VERSION 5.8 ;
BUSBITCHARS "[]" ;
DIVIDERCHAR "/" ;
UNITS
    DATABASE MICRONS 1000 ;
END UNITS

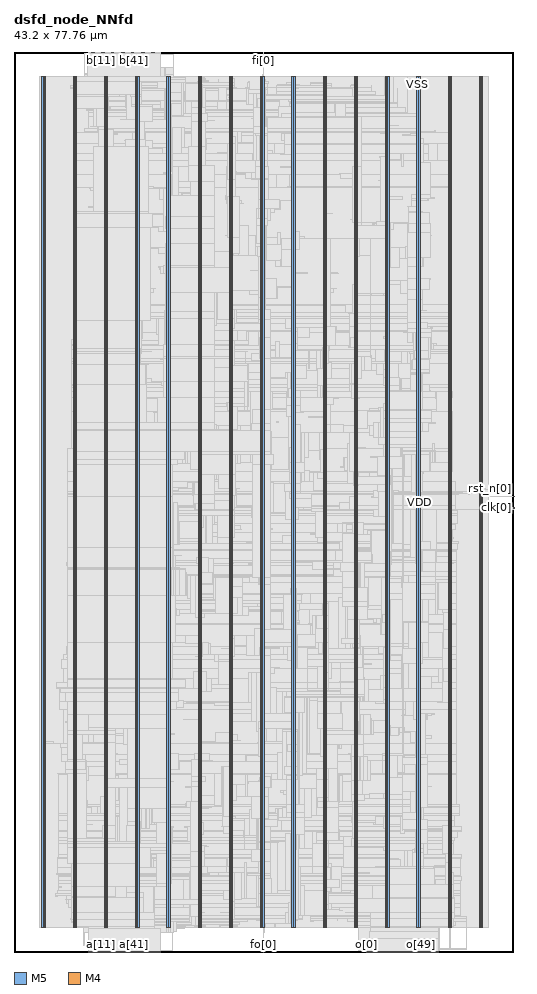
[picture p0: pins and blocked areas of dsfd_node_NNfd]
MACRO dsfd_node_NNfd
  FOREIGN dsfd_node_NNfd 0 0 ;
  CLASS BLOCK ;
  SIZE 43.2 BY 77.76 ;
  PIN a[0]
    DIRECTION INPUT ;
    USE SIGNAL ;
    PORT
      LAYER M5 ;
        RECT  6.432 0 6.456 0.084 ;
    END
  END a[0]
  PIN a[10]
    DIRECTION INPUT ;
    USE SIGNAL ;
    PORT
      LAYER M5 ;
        RECT  7.392 0 7.416 0.084 ;
    END
  END a[10]
  PIN a[11]
    DIRECTION INPUT ;
    USE SIGNAL ;
    PORT
      LAYER M5 ;
        RECT  7.488 0 7.512 0.084 ;
    END
  END a[11]
  PIN a[12]
    DIRECTION INPUT ;
    USE SIGNAL ;
    PORT
      LAYER M5 ;
        RECT  7.584 0 7.608 0.084 ;
    END
  END a[12]
  PIN a[13]
    DIRECTION INPUT ;
    USE SIGNAL ;
    PORT
      LAYER M5 ;
        RECT  7.68 0 7.704 0.084 ;
    END
  END a[13]
  PIN a[14]
    DIRECTION INPUT ;
    USE SIGNAL ;
    PORT
      LAYER M5 ;
        RECT  7.776 0 7.8 0.084 ;
    END
  END a[14]
  PIN a[15]
    DIRECTION INPUT ;
    USE SIGNAL ;
    PORT
      LAYER M5 ;
        RECT  7.872 0 7.896 0.084 ;
    END
  END a[15]
  PIN a[16]
    DIRECTION INPUT ;
    USE SIGNAL ;
    PORT
      LAYER M5 ;
        RECT  7.968 0 7.992 0.084 ;
    END
  END a[16]
  PIN a[17]
    DIRECTION INPUT ;
    USE SIGNAL ;
    PORT
      LAYER M5 ;
        RECT  8.064 0 8.088 0.084 ;
    END
  END a[17]
  PIN a[18]
    DIRECTION INPUT ;
    USE SIGNAL ;
    PORT
      LAYER M5 ;
        RECT  8.16 0 8.184 0.084 ;
    END
  END a[18]
  PIN a[19]
    DIRECTION INPUT ;
    USE SIGNAL ;
    PORT
      LAYER M5 ;
        RECT  8.256 0 8.28 0.084 ;
    END
  END a[19]
  PIN a[1]
    DIRECTION INPUT ;
    USE SIGNAL ;
    PORT
      LAYER M5 ;
        RECT  6.528 0 6.552 0.084 ;
    END
  END a[1]
  PIN a[20]
    DIRECTION INPUT ;
    USE SIGNAL ;
    PORT
      LAYER M5 ;
        RECT  8.352 0 8.376 0.084 ;
    END
  END a[20]
  PIN a[21]
    DIRECTION INPUT ;
    USE SIGNAL ;
    PORT
      LAYER M5 ;
        RECT  8.448 0 8.472 0.084 ;
    END
  END a[21]
  PIN a[22]
    DIRECTION INPUT ;
    USE SIGNAL ;
    PORT
      LAYER M5 ;
        RECT  8.544 0 8.568 0.084 ;
    END
  END a[22]
  PIN a[23]
    DIRECTION INPUT ;
    USE SIGNAL ;
    PORT
      LAYER M5 ;
        RECT  8.64 0 8.664 0.084 ;
    END
  END a[23]
  PIN a[24]
    DIRECTION INPUT ;
    USE SIGNAL ;
    PORT
      LAYER M5 ;
        RECT  8.736 0 8.76 0.084 ;
    END
  END a[24]
  PIN a[25]
    DIRECTION INPUT ;
    USE SIGNAL ;
    PORT
      LAYER M5 ;
        RECT  8.832 0 8.856 0.084 ;
    END
  END a[25]
  PIN a[26]
    DIRECTION INPUT ;
    USE SIGNAL ;
    PORT
      LAYER M5 ;
        RECT  8.928 0 8.952 0.084 ;
    END
  END a[26]
  PIN a[27]
    DIRECTION INPUT ;
    USE SIGNAL ;
    PORT
      LAYER M5 ;
        RECT  9.024 0 9.048 0.084 ;
    END
  END a[27]
  PIN a[28]
    DIRECTION INPUT ;
    USE SIGNAL ;
    PORT
      LAYER M5 ;
        RECT  9.12 0 9.144 0.084 ;
    END
  END a[28]
  PIN a[29]
    DIRECTION INPUT ;
    USE SIGNAL ;
    PORT
      LAYER M5 ;
        RECT  9.216 0 9.24 0.084 ;
    END
  END a[29]
  PIN a[2]
    DIRECTION INPUT ;
    USE SIGNAL ;
    PORT
      LAYER M5 ;
        RECT  6.624 0 6.648 0.084 ;
    END
  END a[2]
  PIN a[30]
    DIRECTION INPUT ;
    USE SIGNAL ;
    PORT
      LAYER M5 ;
        RECT  9.312 0 9.336 0.084 ;
    END
  END a[30]
  PIN a[31]
    DIRECTION INPUT ;
    USE SIGNAL ;
    PORT
      LAYER M5 ;
        RECT  9.408 0 9.432 0.084 ;
    END
  END a[31]
  PIN a[32]
    DIRECTION INPUT ;
    USE SIGNAL ;
    PORT
      LAYER M5 ;
        RECT  9.504 0 9.528 0.084 ;
    END
  END a[32]
  PIN a[33]
    DIRECTION INPUT ;
    USE SIGNAL ;
    PORT
      LAYER M5 ;
        RECT  9.6 0 9.624 0.084 ;
    END
  END a[33]
  PIN a[34]
    DIRECTION INPUT ;
    USE SIGNAL ;
    PORT
      LAYER M5 ;
        RECT  9.696 0 9.72 0.084 ;
    END
  END a[34]
  PIN a[35]
    DIRECTION INPUT ;
    USE SIGNAL ;
    PORT
      LAYER M5 ;
        RECT  9.792 0 9.816 0.084 ;
    END
  END a[35]
  PIN a[36]
    DIRECTION INPUT ;
    USE SIGNAL ;
    PORT
      LAYER M5 ;
        RECT  9.888 0 9.912 0.084 ;
    END
  END a[36]
  PIN a[37]
    DIRECTION INPUT ;
    USE SIGNAL ;
    PORT
      LAYER M5 ;
        RECT  9.984 0 10.008 0.084 ;
    END
  END a[37]
  PIN a[38]
    DIRECTION INPUT ;
    USE SIGNAL ;
    PORT
      LAYER M5 ;
        RECT  10.08 0 10.104 0.084 ;
    END
  END a[38]
  PIN a[39]
    DIRECTION INPUT ;
    USE SIGNAL ;
    PORT
      LAYER M5 ;
        RECT  10.176 0 10.2 0.084 ;
    END
  END a[39]
  PIN a[3]
    DIRECTION INPUT ;
    USE SIGNAL ;
    PORT
      LAYER M5 ;
        RECT  6.72 0 6.744 0.084 ;
    END
  END a[3]
  PIN a[40]
    DIRECTION INPUT ;
    USE SIGNAL ;
    PORT
      LAYER M5 ;
        RECT  10.272 0 10.296 0.084 ;
    END
  END a[40]
  PIN a[41]
    DIRECTION INPUT ;
    USE SIGNAL ;
    PORT
      LAYER M5 ;
        RECT  10.368 0 10.392 0.084 ;
    END
  END a[41]
  PIN a[42]
    DIRECTION INPUT ;
    USE SIGNAL ;
    PORT
      LAYER M5 ;
        RECT  10.464 0 10.488 0.084 ;
    END
  END a[42]
  PIN a[43]
    DIRECTION INPUT ;
    USE SIGNAL ;
    PORT
      LAYER M5 ;
        RECT  10.56 0 10.584 0.084 ;
    END
  END a[43]
  PIN a[44]
    DIRECTION INPUT ;
    USE SIGNAL ;
    PORT
      LAYER M5 ;
        RECT  10.656 0 10.68 0.084 ;
    END
  END a[44]
  PIN a[45]
    DIRECTION INPUT ;
    USE SIGNAL ;
    PORT
      LAYER M5 ;
        RECT  10.752 0 10.776 0.084 ;
    END
  END a[45]
  PIN a[46]
    DIRECTION INPUT ;
    USE SIGNAL ;
    PORT
      LAYER M5 ;
        RECT  10.848 0 10.872 0.084 ;
    END
  END a[46]
  PIN a[47]
    DIRECTION INPUT ;
    USE SIGNAL ;
    PORT
      LAYER M5 ;
        RECT  10.944 0 10.968 0.084 ;
    END
  END a[47]
  PIN a[48]
    DIRECTION INPUT ;
    USE SIGNAL ;
    PORT
      LAYER M5 ;
        RECT  11.04 0 11.064 0.084 ;
    END
  END a[48]
  PIN a[49]
    DIRECTION INPUT ;
    USE SIGNAL ;
    PORT
      LAYER M5 ;
        RECT  11.136 0 11.16 0.084 ;
    END
  END a[49]
  PIN a[4]
    DIRECTION INPUT ;
    USE SIGNAL ;
    PORT
      LAYER M5 ;
        RECT  6.816 0 6.84 0.084 ;
    END
  END a[4]
  PIN a[50]
    DIRECTION INPUT ;
    USE SIGNAL ;
    PORT
      LAYER M5 ;
        RECT  11.232 0 11.256 0.084 ;
    END
  END a[50]
  PIN a[51]
    DIRECTION INPUT ;
    USE SIGNAL ;
    PORT
      LAYER M5 ;
        RECT  11.328 0 11.352 0.084 ;
    END
  END a[51]
  PIN a[52]
    DIRECTION INPUT ;
    USE SIGNAL ;
    PORT
      LAYER M5 ;
        RECT  11.424 0 11.448 0.084 ;
    END
  END a[52]
  PIN a[53]
    DIRECTION INPUT ;
    USE SIGNAL ;
    PORT
      LAYER M5 ;
        RECT  11.52 0 11.544 0.084 ;
    END
  END a[53]
  PIN a[54]
    DIRECTION INPUT ;
    USE SIGNAL ;
    PORT
      LAYER M5 ;
        RECT  11.616 0 11.64 0.084 ;
    END
  END a[54]
  PIN a[55]
    DIRECTION INPUT ;
    USE SIGNAL ;
    PORT
      LAYER M5 ;
        RECT  11.712 0 11.736 0.084 ;
    END
  END a[55]
  PIN a[56]
    DIRECTION INPUT ;
    USE SIGNAL ;
    PORT
      LAYER M5 ;
        RECT  11.808 0 11.832 0.084 ;
    END
  END a[56]
  PIN a[57]
    DIRECTION INPUT ;
    USE SIGNAL ;
    PORT
      LAYER M5 ;
        RECT  11.904 0 11.928 0.084 ;
    END
  END a[57]
  PIN a[58]
    DIRECTION INPUT ;
    USE SIGNAL ;
    PORT
      LAYER M5 ;
        RECT  12 0 12.024 0.084 ;
    END
  END a[58]
  PIN a[59]
    DIRECTION INPUT ;
    USE SIGNAL ;
    PORT
      LAYER M5 ;
        RECT  12.096 0 12.12 0.084 ;
    END
  END a[59]
  PIN a[5]
    DIRECTION INPUT ;
    USE SIGNAL ;
    PORT
      LAYER M5 ;
        RECT  6.912 0 6.936 0.084 ;
    END
  END a[5]
  PIN a[60]
    DIRECTION INPUT ;
    USE SIGNAL ;
    PORT
      LAYER M5 ;
        RECT  12.192 0 12.216 0.084 ;
    END
  END a[60]
  PIN a[61]
    DIRECTION INPUT ;
    USE SIGNAL ;
    PORT
      LAYER M5 ;
        RECT  12.288 0 12.312 0.084 ;
    END
  END a[61]
  PIN a[62]
    DIRECTION INPUT ;
    USE SIGNAL ;
    PORT
      LAYER M5 ;
        RECT  12.384 0 12.408 0.084 ;
    END
  END a[62]
  PIN a[63]
    DIRECTION INPUT ;
    USE SIGNAL ;
    PORT
      LAYER M5 ;
        RECT  12.48 0 12.504 0.084 ;
    END
  END a[63]
  PIN a[64]
    DIRECTION INPUT ;
    USE SIGNAL ;
    PORT
      LAYER M5 ;
        RECT  12.576 0 12.6 0.084 ;
    END
  END a[64]
  PIN a[65]
    DIRECTION INPUT ;
    USE SIGNAL ;
    PORT
      LAYER M5 ;
        RECT  12.672 0 12.696 0.084 ;
    END
  END a[65]
  PIN a[6]
    DIRECTION INPUT ;
    USE SIGNAL ;
    PORT
      LAYER M5 ;
        RECT  7.008 0 7.032 0.084 ;
    END
  END a[6]
  PIN a[7]
    DIRECTION INPUT ;
    USE SIGNAL ;
    PORT
      LAYER M5 ;
        RECT  7.104 0 7.128 0.084 ;
    END
  END a[7]
  PIN a[8]
    DIRECTION INPUT ;
    USE SIGNAL ;
    PORT
      LAYER M5 ;
        RECT  7.2 0 7.224 0.084 ;
    END
  END a[8]
  PIN a[9]
    DIRECTION INPUT ;
    USE SIGNAL ;
    PORT
      LAYER M5 ;
        RECT  7.296 0 7.32 0.084 ;
    END
  END a[9]
  PIN b[0]
    DIRECTION INPUT ;
    USE SIGNAL ;
    PORT
      LAYER M5 ;
        RECT  6.432 77.676 6.456 77.76 ;
    END
  END b[0]
  PIN b[10]
    DIRECTION INPUT ;
    USE SIGNAL ;
    PORT
      LAYER M5 ;
        RECT  7.392 77.676 7.416 77.76 ;
    END
  END b[10]
  PIN b[11]
    DIRECTION INPUT ;
    USE SIGNAL ;
    PORT
      LAYER M5 ;
        RECT  7.488 77.676 7.512 77.76 ;
    END
  END b[11]
  PIN b[12]
    DIRECTION INPUT ;
    USE SIGNAL ;
    PORT
      LAYER M5 ;
        RECT  7.584 77.676 7.608 77.76 ;
    END
  END b[12]
  PIN b[13]
    DIRECTION INPUT ;
    USE SIGNAL ;
    PORT
      LAYER M5 ;
        RECT  7.68 77.676 7.704 77.76 ;
    END
  END b[13]
  PIN b[14]
    DIRECTION INPUT ;
    USE SIGNAL ;
    PORT
      LAYER M5 ;
        RECT  7.776 77.676 7.8 77.76 ;
    END
  END b[14]
  PIN b[15]
    DIRECTION INPUT ;
    USE SIGNAL ;
    PORT
      LAYER M5 ;
        RECT  7.872 77.676 7.896 77.76 ;
    END
  END b[15]
  PIN b[16]
    DIRECTION INPUT ;
    USE SIGNAL ;
    PORT
      LAYER M5 ;
        RECT  7.968 77.676 7.992 77.76 ;
    END
  END b[16]
  PIN b[17]
    DIRECTION INPUT ;
    USE SIGNAL ;
    PORT
      LAYER M5 ;
        RECT  8.064 77.676 8.088 77.76 ;
    END
  END b[17]
  PIN b[18]
    DIRECTION INPUT ;
    USE SIGNAL ;
    PORT
      LAYER M5 ;
        RECT  8.16 77.676 8.184 77.76 ;
    END
  END b[18]
  PIN b[19]
    DIRECTION INPUT ;
    USE SIGNAL ;
    PORT
      LAYER M5 ;
        RECT  8.256 77.676 8.28 77.76 ;
    END
  END b[19]
  PIN b[1]
    DIRECTION INPUT ;
    USE SIGNAL ;
    PORT
      LAYER M5 ;
        RECT  6.528 77.676 6.552 77.76 ;
    END
  END b[1]
  PIN b[20]
    DIRECTION INPUT ;
    USE SIGNAL ;
    PORT
      LAYER M5 ;
        RECT  8.352 77.676 8.376 77.76 ;
    END
  END b[20]
  PIN b[21]
    DIRECTION INPUT ;
    USE SIGNAL ;
    PORT
      LAYER M5 ;
        RECT  8.448 77.676 8.472 77.76 ;
    END
  END b[21]
  PIN b[22]
    DIRECTION INPUT ;
    USE SIGNAL ;
    PORT
      LAYER M5 ;
        RECT  8.544 77.676 8.568 77.76 ;
    END
  END b[22]
  PIN b[23]
    DIRECTION INPUT ;
    USE SIGNAL ;
    PORT
      LAYER M5 ;
        RECT  8.64 77.676 8.664 77.76 ;
    END
  END b[23]
  PIN b[24]
    DIRECTION INPUT ;
    USE SIGNAL ;
    PORT
      LAYER M5 ;
        RECT  8.736 77.676 8.76 77.76 ;
    END
  END b[24]
  PIN b[25]
    DIRECTION INPUT ;
    USE SIGNAL ;
    PORT
      LAYER M5 ;
        RECT  8.832 77.676 8.856 77.76 ;
    END
  END b[25]
  PIN b[26]
    DIRECTION INPUT ;
    USE SIGNAL ;
    PORT
      LAYER M5 ;
        RECT  8.928 77.676 8.952 77.76 ;
    END
  END b[26]
  PIN b[27]
    DIRECTION INPUT ;
    USE SIGNAL ;
    PORT
      LAYER M5 ;
        RECT  9.024 77.676 9.048 77.76 ;
    END
  END b[27]
  PIN b[28]
    DIRECTION INPUT ;
    USE SIGNAL ;
    PORT
      LAYER M5 ;
        RECT  9.12 77.676 9.144 77.76 ;
    END
  END b[28]
  PIN b[29]
    DIRECTION INPUT ;
    USE SIGNAL ;
    PORT
      LAYER M5 ;
        RECT  9.216 77.676 9.24 77.76 ;
    END
  END b[29]
  PIN b[2]
    DIRECTION INPUT ;
    USE SIGNAL ;
    PORT
      LAYER M5 ;
        RECT  6.624 77.676 6.648 77.76 ;
    END
  END b[2]
  PIN b[30]
    DIRECTION INPUT ;
    USE SIGNAL ;
    PORT
      LAYER M5 ;
        RECT  9.312 77.676 9.336 77.76 ;
    END
  END b[30]
  PIN b[31]
    DIRECTION INPUT ;
    USE SIGNAL ;
    PORT
      LAYER M5 ;
        RECT  9.408 77.676 9.432 77.76 ;
    END
  END b[31]
  PIN b[32]
    DIRECTION INPUT ;
    USE SIGNAL ;
    PORT
      LAYER M5 ;
        RECT  9.504 77.676 9.528 77.76 ;
    END
  END b[32]
  PIN b[33]
    DIRECTION INPUT ;
    USE SIGNAL ;
    PORT
      LAYER M5 ;
        RECT  9.6 77.676 9.624 77.76 ;
    END
  END b[33]
  PIN b[34]
    DIRECTION INPUT ;
    USE SIGNAL ;
    PORT
      LAYER M5 ;
        RECT  9.696 77.676 9.72 77.76 ;
    END
  END b[34]
  PIN b[35]
    DIRECTION INPUT ;
    USE SIGNAL ;
    PORT
      LAYER M5 ;
        RECT  9.792 77.676 9.816 77.76 ;
    END
  END b[35]
  PIN b[36]
    DIRECTION INPUT ;
    USE SIGNAL ;
    PORT
      LAYER M5 ;
        RECT  9.888 77.676 9.912 77.76 ;
    END
  END b[36]
  PIN b[37]
    DIRECTION INPUT ;
    USE SIGNAL ;
    PORT
      LAYER M5 ;
        RECT  9.984 77.676 10.008 77.76 ;
    END
  END b[37]
  PIN b[38]
    DIRECTION INPUT ;
    USE SIGNAL ;
    PORT
      LAYER M5 ;
        RECT  10.08 77.676 10.104 77.76 ;
    END
  END b[38]
  PIN b[39]
    DIRECTION INPUT ;
    USE SIGNAL ;
    PORT
      LAYER M5 ;
        RECT  10.176 77.676 10.2 77.76 ;
    END
  END b[39]
  PIN b[3]
    DIRECTION INPUT ;
    USE SIGNAL ;
    PORT
      LAYER M5 ;
        RECT  6.72 77.676 6.744 77.76 ;
    END
  END b[3]
  PIN b[40]
    DIRECTION INPUT ;
    USE SIGNAL ;
    PORT
      LAYER M5 ;
        RECT  10.272 77.676 10.296 77.76 ;
    END
  END b[40]
  PIN b[41]
    DIRECTION INPUT ;
    USE SIGNAL ;
    PORT
      LAYER M5 ;
        RECT  10.368 77.676 10.392 77.76 ;
    END
  END b[41]
  PIN b[42]
    DIRECTION INPUT ;
    USE SIGNAL ;
    PORT
      LAYER M5 ;
        RECT  10.464 77.676 10.488 77.76 ;
    END
  END b[42]
  PIN b[43]
    DIRECTION INPUT ;
    USE SIGNAL ;
    PORT
      LAYER M5 ;
        RECT  10.56 77.676 10.584 77.76 ;
    END
  END b[43]
  PIN b[44]
    DIRECTION INPUT ;
    USE SIGNAL ;
    PORT
      LAYER M5 ;
        RECT  10.656 77.676 10.68 77.76 ;
    END
  END b[44]
  PIN b[45]
    DIRECTION INPUT ;
    USE SIGNAL ;
    PORT
      LAYER M5 ;
        RECT  10.752 77.676 10.776 77.76 ;
    END
  END b[45]
  PIN b[46]
    DIRECTION INPUT ;
    USE SIGNAL ;
    PORT
      LAYER M5 ;
        RECT  10.848 77.676 10.872 77.76 ;
    END
  END b[46]
  PIN b[47]
    DIRECTION INPUT ;
    USE SIGNAL ;
    PORT
      LAYER M5 ;
        RECT  10.944 77.676 10.968 77.76 ;
    END
  END b[47]
  PIN b[48]
    DIRECTION INPUT ;
    USE SIGNAL ;
    PORT
      LAYER M5 ;
        RECT  11.04 77.676 11.064 77.76 ;
    END
  END b[48]
  PIN b[49]
    DIRECTION INPUT ;
    USE SIGNAL ;
    PORT
      LAYER M5 ;
        RECT  11.136 77.676 11.16 77.76 ;
    END
  END b[49]
  PIN b[4]
    DIRECTION INPUT ;
    USE SIGNAL ;
    PORT
      LAYER M5 ;
        RECT  6.816 77.676 6.84 77.76 ;
    END
  END b[4]
  PIN b[50]
    DIRECTION INPUT ;
    USE SIGNAL ;
    PORT
      LAYER M5 ;
        RECT  11.232 77.676 11.256 77.76 ;
    END
  END b[50]
  PIN b[51]
    DIRECTION INPUT ;
    USE SIGNAL ;
    PORT
      LAYER M5 ;
        RECT  11.328 77.676 11.352 77.76 ;
    END
  END b[51]
  PIN b[52]
    DIRECTION INPUT ;
    USE SIGNAL ;
    PORT
      LAYER M5 ;
        RECT  11.424 77.676 11.448 77.76 ;
    END
  END b[52]
  PIN b[53]
    DIRECTION INPUT ;
    USE SIGNAL ;
    PORT
      LAYER M5 ;
        RECT  11.52 77.676 11.544 77.76 ;
    END
  END b[53]
  PIN b[54]
    DIRECTION INPUT ;
    USE SIGNAL ;
    PORT
      LAYER M5 ;
        RECT  11.616 77.676 11.64 77.76 ;
    END
  END b[54]
  PIN b[55]
    DIRECTION INPUT ;
    USE SIGNAL ;
    PORT
      LAYER M5 ;
        RECT  11.712 77.676 11.736 77.76 ;
    END
  END b[55]
  PIN b[56]
    DIRECTION INPUT ;
    USE SIGNAL ;
    PORT
      LAYER M5 ;
        RECT  11.808 77.676 11.832 77.76 ;
    END
  END b[56]
  PIN b[57]
    DIRECTION INPUT ;
    USE SIGNAL ;
    PORT
      LAYER M5 ;
        RECT  11.904 77.676 11.928 77.76 ;
    END
  END b[57]
  PIN b[58]
    DIRECTION INPUT ;
    USE SIGNAL ;
    PORT
      LAYER M5 ;
        RECT  12 77.676 12.024 77.76 ;
    END
  END b[58]
  PIN b[59]
    DIRECTION INPUT ;
    USE SIGNAL ;
    PORT
      LAYER M5 ;
        RECT  12.096 77.676 12.12 77.76 ;
    END
  END b[59]
  PIN b[5]
    DIRECTION INPUT ;
    USE SIGNAL ;
    PORT
      LAYER M5 ;
        RECT  6.912 77.676 6.936 77.76 ;
    END
  END b[5]
  PIN b[60]
    DIRECTION INPUT ;
    USE SIGNAL ;
    PORT
      LAYER M5 ;
        RECT  12.192 77.676 12.216 77.76 ;
    END
  END b[60]
  PIN b[61]
    DIRECTION INPUT ;
    USE SIGNAL ;
    PORT
      LAYER M5 ;
        RECT  12.288 77.676 12.312 77.76 ;
    END
  END b[61]
  PIN b[62]
    DIRECTION INPUT ;
    USE SIGNAL ;
    PORT
      LAYER M5 ;
        RECT  12.384 77.676 12.408 77.76 ;
    END
  END b[62]
  PIN b[63]
    DIRECTION INPUT ;
    USE SIGNAL ;
    PORT
      LAYER M5 ;
        RECT  12.48 77.676 12.504 77.76 ;
    END
  END b[63]
  PIN b[64]
    DIRECTION INPUT ;
    USE SIGNAL ;
    PORT
      LAYER M5 ;
        RECT  12.576 77.676 12.6 77.76 ;
    END
  END b[64]
  PIN b[65]
    DIRECTION INPUT ;
    USE SIGNAL ;
    PORT
      LAYER M5 ;
        RECT  12.672 77.676 12.696 77.76 ;
    END
  END b[65]
  PIN b[6]
    DIRECTION INPUT ;
    USE SIGNAL ;
    PORT
      LAYER M5 ;
        RECT  7.008 77.676 7.032 77.76 ;
    END
  END b[6]
  PIN b[7]
    DIRECTION INPUT ;
    USE SIGNAL ;
    PORT
      LAYER M5 ;
        RECT  7.104 77.676 7.128 77.76 ;
    END
  END b[7]
  PIN b[8]
    DIRECTION INPUT ;
    USE SIGNAL ;
    PORT
      LAYER M5 ;
        RECT  7.2 77.676 7.224 77.76 ;
    END
  END b[8]
  PIN b[9]
    DIRECTION INPUT ;
    USE SIGNAL ;
    PORT
      LAYER M5 ;
        RECT  7.296 77.676 7.32 77.76 ;
    END
  END b[9]
  PIN clk[0]
    DIRECTION INPUT ;
    USE SIGNAL ;
    PORT
      LAYER M4 ;
        RECT  43.116 38.352 43.2 38.376 ;
    END
  END clk[0]
  PIN fi[0]
    DIRECTION INPUT ;
    USE SIGNAL ;
    PORT
      LAYER M5 ;
        RECT  21.552 77.676 21.576 77.76 ;
    END
  END fi[0]
  PIN fo[0]
    DIRECTION OUTPUT ;
    USE SIGNAL ;
    PORT
      LAYER M5 ;
        RECT  21.552 0 21.576 0.084 ;
    END
  END fo[0]
  PIN o[0]
    DIRECTION OUTPUT ;
    USE SIGNAL ;
    PORT
      LAYER M5 ;
        RECT  30.432 0 30.456 0.084 ;
    END
  END o[0]
  PIN o[10]
    DIRECTION OUTPUT ;
    USE SIGNAL ;
    PORT
      LAYER M5 ;
        RECT  31.392 0 31.416 0.084 ;
    END
  END o[10]
  PIN o[11]
    DIRECTION OUTPUT ;
    USE SIGNAL ;
    PORT
      LAYER M5 ;
        RECT  31.488 0 31.512 0.084 ;
    END
  END o[11]
  PIN o[12]
    DIRECTION OUTPUT ;
    USE SIGNAL ;
    PORT
      LAYER M5 ;
        RECT  31.584 0 31.608 0.084 ;
    END
  END o[12]
  PIN o[13]
    DIRECTION OUTPUT ;
    USE SIGNAL ;
    PORT
      LAYER M5 ;
        RECT  31.68 0 31.704 0.084 ;
    END
  END o[13]
  PIN o[14]
    DIRECTION OUTPUT ;
    USE SIGNAL ;
    PORT
      LAYER M5 ;
        RECT  31.776 0 31.8 0.084 ;
    END
  END o[14]
  PIN o[15]
    DIRECTION OUTPUT ;
    USE SIGNAL ;
    PORT
      LAYER M5 ;
        RECT  31.872 0 31.896 0.084 ;
    END
  END o[15]
  PIN o[16]
    DIRECTION OUTPUT ;
    USE SIGNAL ;
    PORT
      LAYER M5 ;
        RECT  31.968 0 31.992 0.084 ;
    END
  END o[16]
  PIN o[17]
    DIRECTION OUTPUT ;
    USE SIGNAL ;
    PORT
      LAYER M5 ;
        RECT  32.064 0 32.088 0.084 ;
    END
  END o[17]
  PIN o[18]
    DIRECTION OUTPUT ;
    USE SIGNAL ;
    PORT
      LAYER M5 ;
        RECT  32.16 0 32.184 0.084 ;
    END
  END o[18]
  PIN o[19]
    DIRECTION OUTPUT ;
    USE SIGNAL ;
    PORT
      LAYER M5 ;
        RECT  32.256 0 32.28 0.084 ;
    END
  END o[19]
  PIN o[1]
    DIRECTION OUTPUT ;
    USE SIGNAL ;
    PORT
      LAYER M5 ;
        RECT  30.528 0 30.552 0.084 ;
    END
  END o[1]
  PIN o[20]
    DIRECTION OUTPUT ;
    USE SIGNAL ;
    PORT
      LAYER M5 ;
        RECT  32.352 0 32.376 0.084 ;
    END
  END o[20]
  PIN o[21]
    DIRECTION OUTPUT ;
    USE SIGNAL ;
    PORT
      LAYER M5 ;
        RECT  32.448 0 32.472 0.084 ;
    END
  END o[21]
  PIN o[22]
    DIRECTION OUTPUT ;
    USE SIGNAL ;
    PORT
      LAYER M5 ;
        RECT  32.544 0 32.568 0.084 ;
    END
  END o[22]
  PIN o[23]
    DIRECTION OUTPUT ;
    USE SIGNAL ;
    PORT
      LAYER M5 ;
        RECT  32.64 0 32.664 0.084 ;
    END
  END o[23]
  PIN o[24]
    DIRECTION OUTPUT ;
    USE SIGNAL ;
    PORT
      LAYER M5 ;
        RECT  32.736 0 32.76 0.084 ;
    END
  END o[24]
  PIN o[25]
    DIRECTION OUTPUT ;
    USE SIGNAL ;
    PORT
      LAYER M5 ;
        RECT  32.832 0 32.856 0.084 ;
    END
  END o[25]
  PIN o[26]
    DIRECTION OUTPUT ;
    USE SIGNAL ;
    PORT
      LAYER M5 ;
        RECT  32.928 0 32.952 0.084 ;
    END
  END o[26]
  PIN o[27]
    DIRECTION OUTPUT ;
    USE SIGNAL ;
    PORT
      LAYER M5 ;
        RECT  33.024 0 33.048 0.084 ;
    END
  END o[27]
  PIN o[28]
    DIRECTION OUTPUT ;
    USE SIGNAL ;
    PORT
      LAYER M5 ;
        RECT  33.12 0 33.144 0.084 ;
    END
  END o[28]
  PIN o[29]
    DIRECTION OUTPUT ;
    USE SIGNAL ;
    PORT
      LAYER M5 ;
        RECT  33.216 0 33.24 0.084 ;
    END
  END o[29]
  PIN o[2]
    DIRECTION OUTPUT ;
    USE SIGNAL ;
    PORT
      LAYER M5 ;
        RECT  30.624 0 30.648 0.084 ;
    END
  END o[2]
  PIN o[30]
    DIRECTION OUTPUT ;
    USE SIGNAL ;
    PORT
      LAYER M5 ;
        RECT  33.312 0 33.336 0.084 ;
    END
  END o[30]
  PIN o[31]
    DIRECTION OUTPUT ;
    USE SIGNAL ;
    PORT
      LAYER M5 ;
        RECT  33.408 0 33.432 0.084 ;
    END
  END o[31]
  PIN o[32]
    DIRECTION OUTPUT ;
    USE SIGNAL ;
    PORT
      LAYER M5 ;
        RECT  33.504 0 33.528 0.084 ;
    END
  END o[32]
  PIN o[33]
    DIRECTION OUTPUT ;
    USE SIGNAL ;
    PORT
      LAYER M5 ;
        RECT  33.6 0 33.624 0.084 ;
    END
  END o[33]
  PIN o[34]
    DIRECTION OUTPUT ;
    USE SIGNAL ;
    PORT
      LAYER M5 ;
        RECT  33.696 0 33.72 0.084 ;
    END
  END o[34]
  PIN o[35]
    DIRECTION OUTPUT ;
    USE SIGNAL ;
    PORT
      LAYER M5 ;
        RECT  33.792 0 33.816 0.084 ;
    END
  END o[35]
  PIN o[36]
    DIRECTION OUTPUT ;
    USE SIGNAL ;
    PORT
      LAYER M5 ;
        RECT  33.888 0 33.912 0.084 ;
    END
  END o[36]
  PIN o[37]
    DIRECTION OUTPUT ;
    USE SIGNAL ;
    PORT
      LAYER M5 ;
        RECT  33.984 0 34.008 0.084 ;
    END
  END o[37]
  PIN o[38]
    DIRECTION OUTPUT ;
    USE SIGNAL ;
    PORT
      LAYER M5 ;
        RECT  34.08 0 34.104 0.084 ;
    END
  END o[38]
  PIN o[39]
    DIRECTION OUTPUT ;
    USE SIGNAL ;
    PORT
      LAYER M5 ;
        RECT  34.176 0 34.2 0.084 ;
    END
  END o[39]
  PIN o[3]
    DIRECTION OUTPUT ;
    USE SIGNAL ;
    PORT
      LAYER M5 ;
        RECT  30.72 0 30.744 0.084 ;
    END
  END o[3]
  PIN o[40]
    DIRECTION OUTPUT ;
    USE SIGNAL ;
    PORT
      LAYER M5 ;
        RECT  34.272 0 34.296 0.084 ;
    END
  END o[40]
  PIN o[41]
    DIRECTION OUTPUT ;
    USE SIGNAL ;
    PORT
      LAYER M5 ;
        RECT  34.368 0 34.392 0.084 ;
    END
  END o[41]
  PIN o[42]
    DIRECTION OUTPUT ;
    USE SIGNAL ;
    PORT
      LAYER M5 ;
        RECT  34.464 0 34.488 0.084 ;
    END
  END o[42]
  PIN o[43]
    DIRECTION OUTPUT ;
    USE SIGNAL ;
    PORT
      LAYER M5 ;
        RECT  34.56 0 34.584 0.084 ;
    END
  END o[43]
  PIN o[44]
    DIRECTION OUTPUT ;
    USE SIGNAL ;
    PORT
      LAYER M5 ;
        RECT  34.656 0 34.68 0.084 ;
    END
  END o[44]
  PIN o[45]
    DIRECTION OUTPUT ;
    USE SIGNAL ;
    PORT
      LAYER M5 ;
        RECT  34.752 0 34.776 0.084 ;
    END
  END o[45]
  PIN o[46]
    DIRECTION OUTPUT ;
    USE SIGNAL ;
    PORT
      LAYER M5 ;
        RECT  34.848 0 34.872 0.084 ;
    END
  END o[46]
  PIN o[47]
    DIRECTION OUTPUT ;
    USE SIGNAL ;
    PORT
      LAYER M5 ;
        RECT  34.944 0 34.968 0.084 ;
    END
  END o[47]
  PIN o[48]
    DIRECTION OUTPUT ;
    USE SIGNAL ;
    PORT
      LAYER M5 ;
        RECT  35.04 0 35.064 0.084 ;
    END
  END o[48]
  PIN o[49]
    DIRECTION OUTPUT ;
    USE SIGNAL ;
    PORT
      LAYER M5 ;
        RECT  35.136 0 35.16 0.084 ;
    END
  END o[49]
  PIN o[4]
    DIRECTION OUTPUT ;
    USE SIGNAL ;
    PORT
      LAYER M5 ;
        RECT  30.816 0 30.84 0.084 ;
    END
  END o[4]
  PIN o[50]
    DIRECTION OUTPUT ;
    USE SIGNAL ;
    PORT
      LAYER M5 ;
        RECT  35.232 0 35.256 0.084 ;
    END
  END o[50]
  PIN o[51]
    DIRECTION OUTPUT ;
    USE SIGNAL ;
    PORT
      LAYER M5 ;
        RECT  35.328 0 35.352 0.084 ;
    END
  END o[51]
  PIN o[52]
    DIRECTION OUTPUT ;
    USE SIGNAL ;
    PORT
      LAYER M5 ;
        RECT  35.424 0 35.448 0.084 ;
    END
  END o[52]
  PIN o[53]
    DIRECTION OUTPUT ;
    USE SIGNAL ;
    PORT
      LAYER M5 ;
        RECT  35.52 0 35.544 0.084 ;
    END
  END o[53]
  PIN o[54]
    DIRECTION OUTPUT ;
    USE SIGNAL ;
    PORT
      LAYER M5 ;
        RECT  35.616 0 35.64 0.084 ;
    END
  END o[54]
  PIN o[55]
    DIRECTION OUTPUT ;
    USE SIGNAL ;
    PORT
      LAYER M5 ;
        RECT  35.712 0 35.736 0.084 ;
    END
  END o[55]
  PIN o[56]
    DIRECTION OUTPUT ;
    USE SIGNAL ;
    PORT
      LAYER M5 ;
        RECT  35.808 0 35.832 0.084 ;
    END
  END o[56]
  PIN o[57]
    DIRECTION OUTPUT ;
    USE SIGNAL ;
    PORT
      LAYER M5 ;
        RECT  35.904 0 35.928 0.084 ;
    END
  END o[57]
  PIN o[58]
    DIRECTION OUTPUT ;
    USE SIGNAL ;
    PORT
      LAYER M5 ;
        RECT  36 0 36.024 0.084 ;
    END
  END o[58]
  PIN o[59]
    DIRECTION OUTPUT ;
    USE SIGNAL ;
    PORT
      LAYER M5 ;
        RECT  36.096 0 36.12 0.084 ;
    END
  END o[59]
  PIN o[5]
    DIRECTION OUTPUT ;
    USE SIGNAL ;
    PORT
      LAYER M5 ;
        RECT  30.912 0 30.936 0.084 ;
    END
  END o[5]
  PIN o[60]
    DIRECTION OUTPUT ;
    USE SIGNAL ;
    PORT
      LAYER M5 ;
        RECT  36.192 0 36.216 0.084 ;
    END
  END o[60]
  PIN o[61]
    DIRECTION OUTPUT ;
    USE SIGNAL ;
    PORT
      LAYER M5 ;
        RECT  36.288 0 36.312 0.084 ;
    END
  END o[61]
  PIN o[62]
    DIRECTION OUTPUT ;
    USE SIGNAL ;
    PORT
      LAYER M5 ;
        RECT  36.384 0 36.408 0.084 ;
    END
  END o[62]
  PIN o[63]
    DIRECTION OUTPUT ;
    USE SIGNAL ;
    PORT
      LAYER M5 ;
        RECT  36.48 0 36.504 0.084 ;
    END
  END o[63]
  PIN o[64]
    DIRECTION OUTPUT ;
    USE SIGNAL ;
    PORT
      LAYER M5 ;
        RECT  36.576 0 36.6 0.084 ;
    END
  END o[64]
  PIN o[65]
    DIRECTION OUTPUT ;
    USE SIGNAL ;
    PORT
      LAYER M5 ;
        RECT  36.672 0 36.696 0.084 ;
    END
  END o[65]
  PIN o[6]
    DIRECTION OUTPUT ;
    USE SIGNAL ;
    PORT
      LAYER M5 ;
        RECT  31.008 0 31.032 0.084 ;
    END
  END o[6]
  PIN o[7]
    DIRECTION OUTPUT ;
    USE SIGNAL ;
    PORT
      LAYER M5 ;
        RECT  31.104 0 31.128 0.084 ;
    END
  END o[7]
  PIN o[8]
    DIRECTION OUTPUT ;
    USE SIGNAL ;
    PORT
      LAYER M5 ;
        RECT  31.2 0 31.224 0.084 ;
    END
  END o[8]
  PIN o[9]
    DIRECTION OUTPUT ;
    USE SIGNAL ;
    PORT
      LAYER M5 ;
        RECT  31.296 0 31.32 0.084 ;
    END
  END o[9]
  PIN rst_n[0]
    DIRECTION INPUT ;
    USE SIGNAL ;
    PORT
      LAYER M4 ;
        RECT  43.116 39.36 43.2 39.384 ;
    END
  END rst_n[0]
  PIN VDD
    DIRECTION INOUT ;
    USE POWER ;
    PORT
      LAYER M5 ;
        RECT  40.392 2.151 40.512 75.609 ;
        RECT  37.692 2.151 37.812 75.609 ;
        RECT  34.992 2.151 35.112 75.609 ;
        RECT  32.292 2.151 32.412 75.609 ;
        RECT  29.592 2.151 29.712 75.609 ;
        RECT  26.892 2.151 27.012 75.609 ;
        RECT  24.192 2.151 24.312 75.609 ;
        RECT  21.492 2.151 21.612 75.609 ;
        RECT  18.792 2.151 18.912 75.609 ;
        RECT  16.092 2.151 16.212 75.609 ;
        RECT  13.392 2.151 13.512 75.609 ;
        RECT  10.692 2.151 10.812 75.609 ;
        RECT  7.992 2.151 8.112 75.609 ;
        RECT  5.292 2.151 5.412 75.609 ;
        RECT  2.592 2.151 2.712 75.609 ;
    END
  END VDD
  PIN VSS
    DIRECTION INOUT ;
    USE GROUND ;
    PORT
      LAYER M5 ;
        RECT  40.2 2.137 40.32 75.623 ;
        RECT  37.5 2.137 37.62 75.623 ;
        RECT  34.8 2.137 34.92 75.623 ;
        RECT  32.1 2.137 32.22 75.623 ;
        RECT  29.4 2.137 29.52 75.623 ;
        RECT  26.7 2.137 26.82 75.623 ;
        RECT  24 2.137 24.12 75.623 ;
        RECT  21.3 2.137 21.42 75.623 ;
        RECT  18.6 2.137 18.72 75.623 ;
        RECT  15.9 2.137 16.02 75.623 ;
        RECT  13.2 2.137 13.32 75.623 ;
        RECT  10.5 2.137 10.62 75.623 ;
        RECT  7.8 2.137 7.92 75.623 ;
        RECT  5.1 2.137 5.22 75.623 ;
        RECT  2.4 2.137 2.52 75.623 ;
    END
  END VSS
  OBS
    LAYER RVTN ;
     RECT  2.16 2.16 41.04 2.295 ;
     RECT  2.16 2.565 41.04 2.835 ;
     RECT  2.16 3.105 41.04 3.375 ;
     RECT  2.16 3.645 41.04 3.915 ;
     RECT  2.16 4.185 41.04 4.455 ;
     RECT  2.16 4.725 41.04 4.995 ;
     RECT  2.16 5.265 41.04 5.535 ;
     RECT  2.16 5.805 41.04 6.075 ;
     RECT  2.16 6.345 41.04 6.615 ;
     RECT  2.16 6.885 41.04 7.155 ;
     RECT  2.16 7.425 41.04 7.695 ;
     RECT  2.16 7.965 41.04 8.235 ;
     RECT  2.16 8.505 41.04 8.775 ;
     RECT  2.16 9.045 41.04 9.315 ;
     RECT  2.16 9.585 41.04 9.855 ;
     RECT  2.16 10.125 41.04 10.395 ;
     RECT  2.16 10.665 41.04 10.935 ;
     RECT  2.16 11.205 41.04 11.475 ;
     RECT  2.16 11.745 41.04 12.015 ;
     RECT  2.16 12.285 41.04 12.555 ;
     RECT  2.16 12.825 41.04 13.095 ;
     RECT  2.16 13.365 41.04 13.635 ;
     RECT  2.16 13.905 41.04 14.175 ;
     RECT  2.16 14.445 41.04 14.715 ;
     RECT  2.16 14.985 41.04 15.255 ;
     RECT  2.16 15.525 41.04 15.795 ;
     RECT  2.16 16.065 41.04 16.335 ;
     RECT  2.16 16.605 41.04 16.875 ;
     RECT  2.16 17.145 41.04 17.415 ;
     RECT  2.16 17.685 41.04 17.955 ;
     RECT  2.16 18.225 41.04 18.495 ;
     RECT  2.16 18.765 41.04 19.035 ;
     RECT  2.16 19.305 41.04 19.575 ;
     RECT  2.16 19.845 41.04 20.115 ;
     RECT  2.16 20.385 41.04 20.655 ;
     RECT  2.16 20.925 41.04 21.195 ;
     RECT  2.16 21.465 41.04 21.735 ;
     RECT  2.16 22.005 41.04 22.275 ;
     RECT  2.16 22.545 41.04 22.815 ;
     RECT  2.16 23.085 41.04 23.355 ;
     RECT  2.16 23.625 41.04 23.895 ;
     RECT  2.16 24.165 41.04 24.435 ;
     RECT  2.16 24.705 41.04 24.975 ;
     RECT  2.16 25.245 41.04 25.515 ;
     RECT  2.16 25.785 41.04 26.055 ;
     RECT  2.16 26.325 41.04 26.595 ;
     RECT  2.16 26.865 41.04 27.135 ;
     RECT  2.16 27.405 41.04 27.675 ;
     RECT  2.16 27.945 41.04 28.215 ;
     RECT  2.16 28.485 41.04 28.755 ;
     RECT  2.16 29.025 41.04 29.295 ;
     RECT  2.16 29.565 41.04 29.835 ;
     RECT  2.16 30.105 41.04 30.375 ;
     RECT  2.16 30.645 41.04 30.915 ;
     RECT  2.16 31.185 41.04 31.455 ;
     RECT  2.16 31.725 41.04 31.995 ;
     RECT  2.16 32.265 41.04 32.535 ;
     RECT  2.16 32.805 41.04 33.075 ;
     RECT  2.16 33.345 41.04 33.615 ;
     RECT  2.16 33.885 41.04 34.155 ;
     RECT  2.16 34.425 41.04 34.695 ;
     RECT  2.16 34.965 41.04 35.235 ;
     RECT  2.16 35.505 41.04 35.775 ;
     RECT  2.16 36.045 41.04 36.315 ;
     RECT  2.16 36.585 41.04 36.855 ;
     RECT  2.16 37.125 41.04 37.395 ;
     RECT  2.16 37.665 41.04 37.935 ;
     RECT  2.16 38.205 41.04 38.475 ;
     RECT  2.16 38.745 41.04 39.015 ;
     RECT  2.16 39.285 41.04 39.555 ;
     RECT  2.16 39.825 41.04 40.095 ;
     RECT  2.16 40.365 41.04 40.635 ;
     RECT  2.16 40.905 41.04 41.175 ;
     RECT  2.16 41.445 41.04 41.715 ;
     RECT  2.16 41.985 41.04 42.255 ;
     RECT  2.16 42.525 41.04 42.795 ;
     RECT  2.16 43.065 41.04 43.335 ;
     RECT  2.16 43.605 41.04 43.875 ;
     RECT  2.16 44.145 41.04 44.415 ;
     RECT  2.16 44.685 41.04 44.955 ;
     RECT  2.16 45.225 41.04 45.495 ;
     RECT  2.16 45.765 41.04 46.035 ;
     RECT  2.16 46.305 41.04 46.575 ;
     RECT  2.16 46.845 41.04 47.115 ;
     RECT  2.16 47.385 41.04 47.655 ;
     RECT  2.16 47.925 41.04 48.195 ;
     RECT  2.16 48.465 41.04 48.735 ;
     RECT  2.16 49.005 41.04 49.275 ;
     RECT  2.16 49.545 41.04 49.815 ;
     RECT  2.16 50.085 41.04 50.355 ;
     RECT  2.16 50.625 41.04 50.895 ;
     RECT  2.16 51.165 41.04 51.435 ;
     RECT  2.16 51.705 41.04 51.975 ;
     RECT  2.16 52.245 41.04 52.515 ;
     RECT  2.16 52.785 41.04 53.055 ;
     RECT  2.16 53.325 41.04 53.595 ;
     RECT  2.16 53.865 41.04 54.135 ;
     RECT  2.16 54.405 41.04 54.675 ;
     RECT  2.16 54.945 41.04 55.215 ;
     RECT  2.16 55.485 41.04 55.755 ;
     RECT  2.16 56.025 41.04 56.295 ;
     RECT  2.16 56.565 41.04 56.835 ;
     RECT  2.16 57.105 41.04 57.375 ;
     RECT  2.16 57.645 41.04 57.915 ;
     RECT  2.16 58.185 41.04 58.455 ;
     RECT  2.16 58.725 41.04 58.995 ;
     RECT  2.16 59.265 41.04 59.535 ;
     RECT  2.16 59.805 41.04 60.075 ;
     RECT  2.16 60.345 41.04 60.615 ;
     RECT  2.16 60.885 41.04 61.155 ;
     RECT  2.16 61.425 41.04 61.695 ;
     RECT  2.16 61.965 41.04 62.235 ;
     RECT  2.16 62.505 41.04 62.775 ;
     RECT  2.16 63.045 41.04 63.315 ;
     RECT  2.16 63.585 41.04 63.855 ;
     RECT  2.16 64.125 41.04 64.395 ;
     RECT  2.16 64.665 41.04 64.935 ;
     RECT  2.16 65.205 41.04 65.475 ;
     RECT  2.16 65.745 41.04 66.015 ;
     RECT  2.16 66.285 41.04 66.555 ;
     RECT  2.16 66.825 41.04 67.095 ;
     RECT  2.16 67.365 41.04 67.635 ;
     RECT  2.16 67.905 41.04 68.175 ;
     RECT  2.16 68.445 41.04 68.715 ;
     RECT  2.16 68.985 41.04 69.255 ;
     RECT  2.16 69.525 41.04 69.795 ;
     RECT  2.16 70.065 41.04 70.335 ;
     RECT  2.16 70.605 41.04 70.875 ;
     RECT  2.16 71.145 41.04 71.415 ;
     RECT  2.16 71.685 41.04 71.955 ;
     RECT  2.16 72.225 41.04 72.495 ;
     RECT  2.16 72.765 41.04 73.035 ;
     RECT  2.16 73.305 41.04 73.575 ;
     RECT  2.16 73.845 41.04 74.115 ;
     RECT  2.16 74.385 41.04 74.655 ;
     RECT  2.16 74.925 41.04 75.195 ;
     RECT  2.16 75.465 41.04 75.6 ;
    LAYER RVTP ;
     RECT  2.16 2.295 41.04 2.565 ;
     RECT  2.16 2.835 41.04 3.105 ;
     RECT  2.16 3.375 41.04 3.645 ;
     RECT  2.16 3.915 41.04 4.185 ;
     RECT  2.16 4.455 41.04 4.725 ;
     RECT  2.16 4.995 41.04 5.265 ;
     RECT  2.16 5.535 41.04 5.805 ;
     RECT  2.16 6.075 41.04 6.345 ;
     RECT  2.16 6.615 41.04 6.885 ;
     RECT  2.16 7.155 41.04 7.425 ;
     RECT  2.16 7.695 41.04 7.965 ;
     RECT  2.16 8.235 41.04 8.505 ;
     RECT  2.16 8.775 41.04 9.045 ;
     RECT  2.16 9.315 41.04 9.585 ;
     RECT  2.16 9.855 41.04 10.125 ;
     RECT  2.16 10.395 41.04 10.665 ;
     RECT  2.16 10.935 41.04 11.205 ;
     RECT  2.16 11.475 41.04 11.745 ;
     RECT  2.16 12.015 41.04 12.285 ;
     RECT  2.16 12.555 41.04 12.825 ;
     RECT  2.16 13.095 41.04 13.365 ;
     RECT  2.16 13.635 41.04 13.905 ;
     RECT  2.16 14.175 41.04 14.445 ;
     RECT  2.16 14.715 41.04 14.985 ;
     RECT  2.16 15.255 41.04 15.525 ;
     RECT  2.16 15.795 41.04 16.065 ;
     RECT  2.16 16.335 41.04 16.605 ;
     RECT  2.16 16.875 41.04 17.145 ;
     RECT  2.16 17.415 41.04 17.685 ;
     RECT  2.16 17.955 41.04 18.225 ;
     RECT  2.16 18.495 41.04 18.765 ;
     RECT  2.16 19.035 41.04 19.305 ;
     RECT  2.16 19.575 41.04 19.845 ;
     RECT  2.16 20.115 41.04 20.385 ;
     RECT  2.16 20.655 41.04 20.925 ;
     RECT  2.16 21.195 41.04 21.465 ;
     RECT  2.16 21.735 41.04 22.005 ;
     RECT  2.16 22.275 41.04 22.545 ;
     RECT  2.16 22.815 41.04 23.085 ;
     RECT  2.16 23.355 41.04 23.625 ;
     RECT  2.16 23.895 41.04 24.165 ;
     RECT  2.16 24.435 41.04 24.705 ;
     RECT  2.16 24.975 41.04 25.245 ;
     RECT  2.16 25.515 41.04 25.785 ;
     RECT  2.16 26.055 41.04 26.325 ;
     RECT  2.16 26.595 41.04 26.865 ;
     RECT  2.16 27.135 41.04 27.405 ;
     RECT  2.16 27.675 41.04 27.945 ;
     RECT  2.16 28.215 41.04 28.485 ;
     RECT  2.16 28.755 41.04 29.025 ;
     RECT  2.16 29.295 41.04 29.565 ;
     RECT  2.16 29.835 41.04 30.105 ;
     RECT  2.16 30.375 41.04 30.645 ;
     RECT  2.16 30.915 41.04 31.185 ;
     RECT  2.16 31.455 41.04 31.725 ;
     RECT  2.16 31.995 41.04 32.265 ;
     RECT  2.16 32.535 41.04 32.805 ;
     RECT  2.16 33.075 41.04 33.345 ;
     RECT  2.16 33.615 41.04 33.885 ;
     RECT  2.16 34.155 41.04 34.425 ;
     RECT  2.16 34.695 41.04 34.965 ;
     RECT  2.16 35.235 41.04 35.505 ;
     RECT  2.16 35.775 41.04 36.045 ;
     RECT  2.16 36.315 41.04 36.585 ;
     RECT  2.16 36.855 41.04 37.125 ;
     RECT  2.16 37.395 41.04 37.665 ;
     RECT  2.16 37.935 41.04 38.205 ;
     RECT  2.16 38.475 41.04 38.745 ;
     RECT  2.16 39.015 41.04 39.285 ;
     RECT  2.16 39.555 41.04 39.825 ;
     RECT  2.16 40.095 41.04 40.365 ;
     RECT  2.16 40.635 41.04 40.905 ;
     RECT  2.16 41.175 41.04 41.445 ;
     RECT  2.16 41.715 41.04 41.985 ;
     RECT  2.16 42.255 41.04 42.525 ;
     RECT  2.16 42.795 41.04 43.065 ;
     RECT  2.16 43.335 41.04 43.605 ;
     RECT  2.16 43.875 41.04 44.145 ;
     RECT  2.16 44.415 41.04 44.685 ;
     RECT  2.16 44.955 41.04 45.225 ;
     RECT  2.16 45.495 41.04 45.765 ;
     RECT  2.16 46.035 41.04 46.305 ;
     RECT  2.16 46.575 41.04 46.845 ;
     RECT  2.16 47.115 41.04 47.385 ;
     RECT  2.16 47.655 41.04 47.925 ;
     RECT  2.16 48.195 41.04 48.465 ;
     RECT  2.16 48.735 41.04 49.005 ;
     RECT  2.16 49.275 41.04 49.545 ;
     RECT  2.16 49.815 41.04 50.085 ;
     RECT  2.16 50.355 41.04 50.625 ;
     RECT  2.16 50.895 41.04 51.165 ;
     RECT  2.16 51.435 41.04 51.705 ;
     RECT  2.16 51.975 41.04 52.245 ;
     RECT  2.16 52.515 41.04 52.785 ;
     RECT  2.16 53.055 41.04 53.325 ;
     RECT  2.16 53.595 41.04 53.865 ;
     RECT  2.16 54.135 41.04 54.405 ;
     RECT  2.16 54.675 41.04 54.945 ;
     RECT  2.16 55.215 41.04 55.485 ;
     RECT  2.16 55.755 41.04 56.025 ;
     RECT  2.16 56.295 41.04 56.565 ;
     RECT  2.16 56.835 41.04 57.105 ;
     RECT  2.16 57.375 41.04 57.645 ;
     RECT  2.16 57.915 41.04 58.185 ;
     RECT  2.16 58.455 41.04 58.725 ;
     RECT  2.16 58.995 41.04 59.265 ;
     RECT  2.16 59.535 41.04 59.805 ;
     RECT  2.16 60.075 41.04 60.345 ;
     RECT  2.16 60.615 41.04 60.885 ;
     RECT  2.16 61.155 41.04 61.425 ;
     RECT  2.16 61.695 41.04 61.965 ;
     RECT  2.16 62.235 41.04 62.505 ;
     RECT  2.16 62.775 41.04 63.045 ;
     RECT  2.16 63.315 41.04 63.585 ;
     RECT  2.16 63.855 41.04 64.125 ;
     RECT  2.16 64.395 41.04 64.665 ;
     RECT  2.16 64.935 41.04 65.205 ;
     RECT  2.16 65.475 41.04 65.745 ;
     RECT  2.16 66.015 41.04 66.285 ;
     RECT  2.16 66.555 41.04 66.825 ;
     RECT  2.16 67.095 41.04 67.365 ;
     RECT  2.16 67.635 41.04 67.905 ;
     RECT  2.16 68.175 41.04 68.445 ;
     RECT  2.16 68.715 41.04 68.985 ;
     RECT  2.16 69.255 41.04 69.525 ;
     RECT  2.16 69.795 41.04 70.065 ;
     RECT  2.16 70.335 41.04 70.605 ;
     RECT  2.16 70.875 41.04 71.145 ;
     RECT  2.16 71.415 41.04 71.685 ;
     RECT  2.16 71.955 41.04 72.225 ;
     RECT  2.16 72.495 41.04 72.765 ;
     RECT  2.16 73.035 41.04 73.305 ;
     RECT  2.16 73.575 41.04 73.845 ;
     RECT  2.16 74.115 41.04 74.385 ;
     RECT  2.16 74.655 41.04 74.925 ;
     RECT  2.16 75.195 41.04 75.465 ;
    LAYER M1 ;
     RECT  2.16 2.151 41.04 75.609 ;
    LAYER M2 ;
     RECT  2.16 2.151 7.735 75.609 ;
     RECT  7.735 2.151 7.835 75.69 ;
     RECT  7.835 2.151 13.495 75.609 ;
     RECT  13.495 2.151 14.035 75.654 ;
     RECT  14.035 2.034 14.747 75.654 ;
     RECT  14.747 2.151 14.819 75.654 ;
     RECT  14.819 2.151 31.999 75.609 ;
     RECT  31.999 2.106 32.747 75.609 ;
     RECT  32.747 2.151 33.979 75.609 ;
     RECT  34.375 1.152 34.511 1.17 ;
     RECT  33.979 2.106 35.015 75.609 ;
     RECT  35.015 2.151 41.04 75.609 ;
    LAYER M3 ;
     RECT  34.2 0.043 34.218 0.091 ;
     RECT  36.324 0.043 36.342 0.091 ;
     RECT  32.256 0.091 32.67 0.139 ;
     RECT  33.624 0.091 34.506 0.139 ;
     RECT  36.324 0.091 36.522 0.139 ;
     RECT  12.24 0.091 12.258 0.187 ;
     RECT  36.324 0.139 36.774 0.235 ;
     RECT  8.928 0.091 8.946 0.317 ;
     RECT  29.808 0.091 29.826 0.523 ;
     RECT  30.996 0.475 31.014 0.523 ;
     RECT  10.908 0.091 10.926 1.099 ;
     RECT  6.048 0.523 6.066 1.723 ;
     RECT  7.74 0.523 7.758 1.723 ;
     RECT  10.908 1.099 10.962 1.723 ;
     RECT  12.24 0.187 12.654 1.723 ;
     RECT  13.68 0.139 13.698 1.723 ;
     RECT  32.256 0.139 34.506 1.723 ;
     RECT  35.928 0.235 36.774 1.723 ;
     RECT  13.68 1.723 13.77 1.771 ;
     RECT  31.896 1.723 34.506 1.771 ;
     RECT  35.748 1.723 36.774 1.771 ;
     RECT  7.74 1.723 12.654 1.867 ;
     RECT  13.68 1.771 14.022 2.029 ;
     RECT  31.896 1.771 34.686 2.059 ;
     RECT  35.64 1.771 36.774 2.059 ;
     RECT  7.74 1.867 12.726 2.143 ;
     RECT  13.68 2.029 14.742 2.143 ;
     RECT  21.636 1.723 21.654 2.143 ;
     RECT  29.808 0.523 31.014 2.143 ;
     RECT  37.656 0.283 37.674 2.143 ;
     RECT  6.048 1.723 6.75 2.155 ;
     RECT  6.048 2.155 6.894 2.191 ;
     RECT  7.74 2.143 14.742 2.191 ;
     RECT  15.915 2.143 16.005 2.191 ;
     RECT  18.615 2.143 18.705 2.191 ;
     RECT  21.315 2.143 21.654 2.191 ;
     RECT  31.896 2.059 36.774 2.191 ;
     RECT  37.515 2.143 37.674 2.191 ;
     RECT  5.115 2.143 5.205 2.227 ;
     RECT  6.048 2.191 14.742 2.227 ;
     RECT  15.624 2.191 16.005 2.227 ;
     RECT  29.415 2.143 31.014 2.251 ;
     RECT  31.896 2.191 37.998 2.251 ;
     RECT  15.624 2.227 16.578 2.263 ;
     RECT  17.784 2.227 17.802 2.263 ;
     RECT  18.615 2.191 19.314 2.263 ;
     RECT  29.415 2.251 37.998 2.263 ;
     RECT  5.115 2.227 14.742 2.299 ;
     RECT  15.516 2.263 16.578 2.299 ;
     RECT  5.115 2.299 16.578 2.335 ;
     RECT  17.784 2.263 19.314 2.335 ;
     RECT  5.115 2.335 19.314 2.371 ;
     RECT  2.415 2.143 2.505 2.413 ;
     RECT  24.015 2.143 24.105 2.413 ;
     RECT  26.715 2.143 26.805 2.413 ;
     RECT  40.215 2.143 40.305 2.413 ;
     RECT  24.015 2.413 24.297 2.461 ;
     RECT  22.536 2.191 22.554 2.491 ;
     RECT  5.115 2.371 19.494 2.569 ;
     RECT  21.315 2.191 21.726 2.605 ;
     RECT  22.5 2.491 23.202 2.605 ;
     RECT  29.415 2.263 38.142 2.605 ;
     RECT  39.096 0.235 39.114 2.605 ;
     RECT  4.932 2.569 19.494 2.641 ;
     RECT  21.315 2.605 23.202 2.641 ;
     RECT  23.94 2.461 24.354 2.641 ;
     RECT  25.884 2.605 25.902 2.641 ;
     RECT  29.415 2.605 39.114 2.641 ;
     RECT  21.315 2.641 24.354 2.731 ;
     RECT  25.632 2.641 25.902 2.731 ;
     RECT  26.715 2.413 26.997 2.731 ;
     RECT  20.988 2.731 24.534 2.767 ;
     RECT  4.932 2.641 20.178 2.803 ;
     RECT  20.988 2.767 24.894 2.803 ;
     RECT  4.932 2.803 24.894 2.861 ;
     RECT  25.632 2.731 26.997 2.875 ;
     RECT  27.936 2.731 27.954 2.875 ;
     RECT  28.8 2.641 39.114 2.875 ;
     RECT  25.632 2.875 39.114 3.029 ;
     RECT  25.632 3.029 38.97 3.065 ;
     RECT  5.004 2.861 24.894 3.145 ;
     RECT  25.632 3.065 38.61 3.145 ;
     RECT  5.004 3.145 38.61 3.883 ;
     RECT  4.68 3.883 38.61 4.189 ;
     RECT  3.744 4.765 3.762 4.801 ;
     RECT  3.564 4.801 3.762 4.891 ;
     RECT  4.5 4.189 38.61 4.891 ;
     RECT  3.564 4.891 38.61 5.063 ;
     RECT  3.744 5.063 38.61 5.297 ;
     RECT  3.816 5.297 38.61 5.909 ;
     RECT  3.888 5.909 38.61 6.151 ;
     RECT  3.888 6.151 38.682 6.539 ;
     RECT  3.888 6.539 38.574 6.575 ;
     RECT  3.888 6.575 16.902 6.691 ;
     RECT  3.708 6.691 16.902 6.809 ;
     RECT  3.78 6.809 16.902 7.321 ;
     RECT  17.676 6.575 38.574 7.321 ;
     RECT  3.78 7.321 38.574 8.041 ;
     RECT  3.78 8.041 38.646 8.195 ;
     RECT  3.852 8.195 38.646 8.429 ;
     RECT  3.852 8.429 37.962 9.355 ;
     RECT  3.852 9.355 37.998 9.661 ;
     RECT  3.852 9.661 38.034 9.931 ;
     RECT  3.852 9.931 38.286 10.435 ;
     RECT  3.852 10.435 38.646 10.463 ;
     RECT  24.015 10.463 38.646 10.859 ;
     RECT  3.852 10.463 23.13 11.371 ;
     RECT  24.015 10.859 38.07 11.371 ;
     RECT  3.852 11.371 38.07 11.821 ;
     RECT  3.852 11.821 38.466 11.975 ;
     RECT  4.608 11.975 38.466 12.595 ;
     RECT  4.608 12.595 38.502 12.749 ;
     RECT  3.852 11.975 3.87 15.295 ;
     RECT  4.608 12.749 38.25 15.295 ;
     RECT  3.852 15.295 38.25 15.403 ;
     RECT  3.78 15.403 38.25 15.449 ;
     RECT  4.572 15.449 38.25 16.459 ;
     RECT  4.428 16.459 38.25 16.501 ;
     RECT  4.104 16.501 38.25 17.041 ;
     RECT  2.415 2.413 2.697 17.995 ;
     RECT  4.068 17.041 38.25 17.995 ;
     RECT  2.415 17.995 38.25 18.029 ;
     RECT  2.415 18.029 3.402 18.185 ;
     RECT  4.284 18.029 38.25 20.965 ;
     RECT  3.924 20.965 38.25 21.677 ;
     RECT  4.284 21.677 38.25 22.795 ;
     RECT  3.708 22.795 38.25 23.315 ;
     RECT  4.284 23.315 38.25 24.475 ;
     RECT  4.14 24.475 38.25 25.313 ;
     RECT  4.248 25.313 38.25 25.709 ;
     RECT  4.536 25.709 38.25 26.393 ;
     RECT  4.896 26.393 38.25 28.319 ;
     RECT  4.896 28.319 24.642 28.409 ;
     RECT  25.488 28.319 38.25 28.409 ;
     RECT  23.94 28.409 24.642 28.679 ;
     RECT  4.896 28.409 23.094 29.461 ;
     RECT  23.94 28.679 24.606 29.461 ;
     RECT  4.896 29.461 24.606 29.467 ;
     RECT  4.896 29.467 24.678 29.605 ;
     RECT  25.524 28.409 38.25 29.605 ;
     RECT  4.896 29.605 38.25 30.137 ;
     RECT  4.896 30.137 24.822 30.335 ;
     RECT  4.968 30.335 24.822 30.883 ;
     RECT  4.968 30.883 24.894 30.991 ;
     RECT  25.632 30.137 38.25 30.991 ;
     RECT  4.968 30.991 38.25 31.891 ;
     RECT  4.896 31.891 38.25 32.459 ;
     RECT  4.896 32.459 27.63 32.495 ;
     RECT  4.896 32.495 27.594 32.575 ;
     RECT  28.368 32.459 38.25 32.909 ;
     RECT  4.86 32.575 27.594 33.385 ;
     RECT  4.536 33.385 27.594 33.643 ;
     RECT  28.44 32.909 38.25 33.643 ;
     RECT  4.536 33.643 38.25 33.647 ;
     RECT  4.608 33.647 38.25 33.845 ;
     RECT  28.692 33.845 38.25 34.591 ;
     RECT  4.608 33.845 27.81 34.663 ;
     RECT  28.656 34.591 38.25 34.663 ;
     RECT  4.608 34.663 38.25 34.771 ;
     RECT  4.608 34.771 38.286 35.275 ;
     RECT  4.608 35.275 38.394 35.429 ;
     RECT  4.608 35.429 37.926 36.239 ;
     RECT  28.728 36.239 37.926 36.481 ;
     RECT  28.728 36.481 38.106 36.895 ;
     RECT  4.608 36.239 27.918 37.021 ;
     RECT  28.728 36.895 38.142 37.021 ;
     RECT  4.608 37.021 38.142 37.057 ;
     RECT  4.608 37.057 38.286 37.705 ;
     RECT  4.608 37.705 38.358 37.895 ;
     RECT  4.608 37.895 38.286 38.129 ;
     RECT  43.092 38.203 43.11 38.381 ;
     RECT  4.608 38.129 38.178 38.579 ;
     RECT  40.215 2.413 40.497 39.325 ;
     RECT  4.608 38.579 38.142 39.559 ;
     RECT  4.608 39.559 38.43 39.631 ;
     RECT  39.312 39.559 39.33 39.631 ;
     RECT  40.215 39.325 40.842 39.631 ;
     RECT  4.608 39.631 40.842 39.749 ;
     RECT  4.608 39.749 40.77 39.785 ;
     RECT  39.312 39.785 40.77 40.019 ;
     RECT  39.888 40.019 40.698 40.055 ;
     RECT  39.888 40.055 40.497 40.091 ;
     RECT  4.608 39.785 38.178 40.667 ;
     RECT  4.608 40.667 37.797 41.485 ;
     RECT  4.608 41.485 37.854 43.529 ;
     RECT  5.004 43.529 37.854 46.679 ;
     RECT  5.004 46.679 37.797 47.893 ;
     RECT  5.004 47.893 37.854 48.389 ;
     RECT  5.004 48.389 37.797 48.811 ;
     RECT  4.968 48.811 37.797 48.989 ;
     RECT  5.004 48.989 37.797 50.855 ;
     RECT  5.004 50.855 33.462 50.999 ;
     RECT  5.004 50.999 31.23 51.269 ;
     RECT  34.272 50.855 37.797 51.745 ;
     RECT  32.076 50.999 33.462 51.871 ;
     RECT  34.2 51.745 37.797 51.871 ;
     RECT  6.912 51.269 31.23 52.015 ;
     RECT  32.076 51.871 37.797 52.015 ;
     RECT  5.004 51.269 6.174 52.051 ;
     RECT  6.912 52.015 37.797 52.051 ;
     RECT  5.004 52.051 37.797 52.439 ;
     RECT  5.004 52.439 20.25 52.475 ;
     RECT  7.056 52.475 20.25 52.853 ;
     RECT  5.004 52.475 6.174 52.889 ;
     RECT  20.088 52.853 20.25 53.599 ;
     RECT  21.132 52.439 37.797 53.599 ;
     RECT  7.056 52.853 19.314 53.671 ;
     RECT  20.088 53.599 37.797 53.671 ;
     RECT  7.056 53.671 37.797 54.283 ;
     RECT  5.115 52.889 6.174 54.715 ;
     RECT  7.02 54.283 37.797 54.715 ;
     RECT  5.115 54.715 37.797 54.869 ;
     RECT  7.056 54.869 37.797 55.211 ;
     RECT  5.115 54.869 6.174 55.867 ;
     RECT  7.056 55.211 28.638 55.867 ;
     RECT  5.115 55.867 28.638 55.957 ;
     RECT  29.415 55.211 37.797 55.957 ;
     RECT  5.115 55.957 37.797 66.047 ;
     RECT  23.652 66.047 37.797 66.125 ;
     RECT  5.115 66.047 22.698 67.135 ;
     RECT  23.76 66.125 37.797 67.135 ;
     RECT  5.115 67.135 37.797 68.369 ;
     RECT  5.115 68.369 35.874 68.405 ;
     RECT  5.115 68.405 35.802 68.968 ;
     RECT  23.796 68.968 35.802 69.739 ;
     RECT  5.115 68.968 22.482 69.835 ;
     RECT  23.4 69.739 35.802 69.835 ;
     RECT  36.612 68.369 37.797 69.835 ;
     RECT  5.115 69.835 37.797 70.799 ;
     RECT  6.12 70.799 36.378 70.871 ;
     RECT  35.892 70.871 36.378 70.907 ;
     RECT  36.36 70.907 36.378 70.943 ;
     RECT  6.12 70.871 35.097 71.177 ;
     RECT  6.408 71.177 35.097 72.149 ;
     RECT  28.656 72.149 35.097 72.419 ;
     RECT  6.408 72.149 27.738 72.491 ;
     RECT  28.656 72.419 34.002 72.491 ;
     RECT  6.408 72.491 22.914 72.733 ;
     RECT  6.264 72.733 22.914 72.761 ;
     RECT  28.656 72.491 33.786 72.959 ;
     RECT  6.264 72.761 17.586 73.075 ;
     RECT  27.72 72.491 27.738 73.273 ;
     RECT  28.656 72.959 33.174 73.273 ;
     RECT  23.76 72.491 26.997 73.345 ;
     RECT  27.72 73.273 33.174 73.345 ;
     RECT  23.76 73.345 33.174 73.373 ;
     RECT  6.228 73.075 17.586 73.507 ;
     RECT  18.324 72.761 22.914 73.507 ;
     RECT  23.76 73.373 32.397 73.507 ;
     RECT  6.192 73.507 22.914 73.579 ;
     RECT  6.12 73.579 22.914 73.607 ;
     RECT  18.396 73.607 22.914 73.615 ;
     RECT  23.724 73.507 32.397 73.615 ;
     RECT  18.396 73.615 32.397 74.039 ;
     RECT  18.396 74.039 31.23 74.111 ;
     RECT  22.68 74.111 31.23 74.309 ;
     RECT  5.115 70.799 5.397 74.461 ;
     RECT  6.12 73.607 17.658 74.461 ;
     RECT  18.396 74.111 21.87 74.489 ;
     RECT  33.156 73.373 33.174 74.579 ;
     RECT  18.396 74.489 20.322 74.621 ;
     RECT  5.115 74.461 17.658 74.635 ;
     RECT  18.396 74.621 19.206 74.651 ;
     RECT  22.68 74.309 30.906 74.651 ;
     RECT  4.896 74.635 17.658 74.659 ;
     RECT  18.396 74.651 19.062 74.659 ;
     RECT  20.016 74.621 20.322 74.687 ;
     RECT  22.68 74.651 28.278 74.723 ;
     RECT  29.052 74.651 30.906 74.723 ;
     RECT  29.052 74.723 29.697 74.849 ;
     RECT  30.888 74.723 30.906 74.849 ;
     RECT  4.896 74.659 19.062 74.885 ;
     RECT  22.68 74.723 27.414 74.885 ;
     RECT  22.788 74.885 24.678 74.921 ;
     RECT  29.16 74.849 29.697 74.921 ;
     RECT  23.508 74.921 24.678 74.993 ;
     RECT  21.315 74.489 21.87 75.001 ;
     RECT  25.632 74.885 27.414 75.029 ;
     RECT  5.115 74.885 19.062 75.119 ;
     RECT  23.508 74.993 24.297 75.119 ;
     RECT  25.632 75.029 26.997 75.119 ;
     RECT  15.84 75.119 17.694 75.155 ;
     RECT  20.16 74.687 20.322 75.155 ;
     RECT  15.84 75.155 16.83 75.191 ;
     RECT  20.304 75.155 20.322 75.227 ;
     RECT  21.315 75.001 22.014 75.227 ;
     RECT  15.912 75.191 16.83 75.263 ;
     RECT  2.415 18.185 2.697 75.347 ;
     RECT  24.015 75.119 24.297 75.347 ;
     RECT  26.715 75.119 26.997 75.347 ;
     RECT  29.415 74.921 29.697 75.347 ;
     RECT  32.115 74.039 32.397 75.347 ;
     RECT  34.815 72.419 35.097 75.347 ;
     RECT  37.515 70.799 37.797 75.347 ;
     RECT  40.215 40.091 40.497 75.347 ;
     RECT  5.115 75.119 14.814 75.389 ;
     RECT  15.912 75.263 16.542 75.389 ;
     RECT  21.315 75.227 21.726 75.389 ;
     RECT  17.676 75.155 17.694 75.425 ;
     RECT  15.915 75.389 16.542 75.497 ;
     RECT  18.615 75.119 19.062 75.497 ;
     RECT  9.576 75.389 14.814 75.533 ;
     RECT  15.915 75.497 16.47 75.533 ;
     RECT  10.476 75.533 14.814 75.569 ;
     RECT  2.415 75.347 2.505 75.617 ;
     RECT  5.115 75.389 5.205 75.617 ;
     RECT  15.915 75.533 16.005 75.617 ;
     RECT  18.615 75.497 18.705 75.617 ;
     RECT  21.315 75.389 21.582 75.617 ;
     RECT  24.015 75.347 24.105 75.617 ;
     RECT  26.715 75.347 26.805 75.617 ;
     RECT  29.415 75.347 29.505 75.617 ;
     RECT  32.115 75.347 32.205 75.617 ;
     RECT  34.815 75.347 34.905 75.617 ;
     RECT  37.515 75.347 37.605 75.617 ;
     RECT  40.215 75.347 40.305 75.617 ;
     RECT  14.796 75.569 14.814 75.659 ;
     RECT  6.084 75.389 8.838 75.821 ;
     RECT  10.476 75.569 13.77 75.821 ;
     RECT  21.564 75.617 21.582 75.821 ;
     RECT  6.084 75.821 7.398 75.917 ;
     RECT  11.016 75.821 13.77 76.397 ;
     RECT  7.38 75.917 7.398 76.973 ;
     RECT  9.576 75.533 9.738 76.973 ;
     RECT  9.576 76.973 9.594 77.131 ;
     RECT  9.54 77.131 9.594 77.309 ;
     RECT  11.016 76.397 12.654 77.453 ;
     RECT  11.232 77.453 12.654 77.501 ;
     RECT  13.752 76.397 13.77 77.549 ;
     RECT  6.084 75.917 6.102 77.645 ;
     RECT  8.82 77.467 8.838 77.645 ;
     RECT  9.576 77.309 9.594 77.645 ;
     RECT  11.232 77.501 12.33 77.645 ;
    LAYER M4 ;
     RECT  2.408 2.148 2.512 75.612 ;
     RECT  2.512 2.418 2.704 75.342 ;
     RECT  3.913 21.648 3.973 21.672 ;
     RECT  3.697 22.8 3.973 22.824 ;
     RECT  2.704 18 4.057 18.024 ;
     RECT  3.913 5.616 4.097 5.64 ;
     RECT  4.597 7.632 4.633 8.136 ;
     RECT  3.769 15.408 4.633 15.432 ;
     RECT  4.405 16.464 4.633 16.488 ;
     RECT  4.489 4.512 4.669 4.536 ;
     RECT  4.921 2.832 4.933 2.856 ;
     RECT  4.669 3.888 4.933 4.536 ;
     RECT  3.877 11.376 4.981 11.4 ;
     RECT  3.973 21.648 4.993 22.824 ;
     RECT  4.933 2.784 5.108 2.856 ;
     RECT  4.933 3.888 5.108 4.776 ;
     RECT  4.633 7.632 5.108 8.952 ;
     RECT  4.981 11.376 5.108 12.024 ;
     RECT  4.921 14.208 5.108 14.232 ;
     RECT  4.633 15.408 5.108 16.488 ;
     RECT  4.057 17.664 5.108 18.024 ;
     RECT  4.417 19.872 5.108 19.896 ;
     RECT  4.993 21.648 5.108 23.16 ;
     RECT  4.525 25.44 5.108 25.464 ;
     RECT  4.993 29.232 5.108 29.256 ;
     RECT  4.957 31.776 5.108 31.8 ;
     RECT  4.957 34.176 5.108 34.2 ;
     RECT  4.885 35.28 5.108 35.304 ;
     RECT  4.597 39.36 5.108 39.384 ;
     RECT  4.957 48.96 5.108 48.984 ;
     RECT  4.885 74.64 5.108 74.664 ;
     RECT  5.108 2.148 5.212 75.612 ;
     RECT  5.212 2.418 5.404 75.342 ;
     RECT  5.404 48.96 5.465 49.224 ;
     RECT  5.404 9.504 5.555 9.96 ;
     RECT  5.404 12.528 5.555 21.672 ;
     RECT  5.555 14.208 5.603 21.672 ;
     RECT  5.404 28.464 5.681 33.816 ;
     RECT  5.404 74.64 5.681 75.342 ;
     RECT  5.603 14.208 5.789 20.136 ;
     RECT  5.404 42.192 5.789 43.848 ;
     RECT  5.404 35.28 5.808 37.032 ;
     RECT  5.789 14.832 5.825 20.136 ;
     RECT  5.808 35.28 5.861 35.736 ;
     RECT  5.555 9.696 5.891 9.96 ;
     RECT  5.681 28.464 5.905 29.112 ;
     RECT  5.404 63.984 5.939 64.008 ;
     RECT  5.808 37.008 6.041 37.032 ;
     RECT  5.825 14.832 6.149 17.064 ;
     RECT  5.404 2.418 6.181 6.84 ;
     RECT  6.149 14.832 6.227 16.584 ;
     RECT  5.404 22.752 6.275 27.048 ;
     RECT  5.681 30.24 6.275 33.816 ;
     RECT  6.181 2.352 6.325 6.84 ;
     RECT  6.073 77.616 6.325 77.64 ;
     RECT  5.555 12.528 6.329 13.08 ;
     RECT  5.404 45.024 6.365 45.576 ;
     RECT  5.603 21.12 6.469 21.672 ;
     RECT  6.227 14.832 6.473 16.008 ;
     RECT  5.825 18.144 6.473 20.136 ;
     RECT  6.373 54.72 6.509 54.744 ;
     RECT  6.469 21.12 6.515 22.2 ;
     RECT  6.275 23.328 6.545 27.048 ;
     RECT  5.789 42.192 6.545 43.56 ;
     RECT  6.325 77.568 6.563 77.64 ;
     RECT  6.325 2.208 6.613 6.84 ;
     RECT  6.505 66 6.613 66.024 ;
     RECT  6.325 75.552 6.613 75.576 ;
     RECT  6.613 75.552 6.649 75.816 ;
     RECT  6.545 25.536 6.653 27.048 ;
     RECT  6.563 77.568 6.659 77.592 ;
     RECT  6.577 55.872 6.661 55.896 ;
     RECT  5.404 47.04 6.689 47.304 ;
     RECT  6.329 12.528 6.721 12.552 ;
     RECT  6.275 30.24 6.725 32.76 ;
     RECT  5.404 10.992 6.761 11.016 ;
     RECT  6.725 30.528 6.761 32.76 ;
     RECT  6.545 42.768 6.797 43.56 ;
     RECT  6.649 71.328 6.829 71.352 ;
     RECT  5.404 72.912 6.829 72.936 ;
     RECT  6.613 65.808 6.833 66.024 ;
     RECT  6.86 61.536 6.901 61.56 ;
     RECT  6.689 47.04 6.937 47.064 ;
     RECT  6.833 66 6.937 66.024 ;
     RECT  6.901 67.536 6.937 67.56 ;
     RECT  5.404 38.784 6.956 38.808 ;
     RECT  6.649 75.552 6.956 75.912 ;
     RECT  5.404 7.872 6.973 7.944 ;
     RECT  5.465 49.2 6.973 49.224 ;
     RECT  6.613 54.48 7.009 54.504 ;
     RECT  6.973 7.872 7.081 8.424 ;
     RECT  5.891 9.696 7.081 9.768 ;
     RECT  6.956 38.544 7.081 38.808 ;
     RECT  6.973 48.96 7.117 49.224 ;
     RECT  6.86 37.392 7.189 37.416 ;
     RECT  6.721 12 7.225 12.552 ;
     RECT  6.956 75.264 7.235 75.912 ;
     RECT  7.081 38.544 7.244 39.048 ;
     RECT  5.404 40.032 7.244 40.968 ;
     RECT  6.829 71.328 7.244 73.608 ;
     RECT  6.853 69.552 7.285 69.576 ;
     RECT  7.244 70.896 7.285 73.608 ;
     RECT  6.613 1.728 7.34 6.84 ;
     RECT  7.081 7.872 7.34 9.768 ;
     RECT  7.34 76.944 7.427 76.968 ;
     RECT  7.189 27.312 7.429 27.336 ;
     RECT  5.905 28.464 7.429 28.488 ;
     RECT  6.365 45.024 7.441 45.048 ;
     RECT  7.225 11.952 7.477 12.552 ;
     RECT  6.937 66 7.477 67.56 ;
     RECT  7.117 48.96 7.513 49.272 ;
     RECT  7.117 52.992 7.525 53.016 ;
     RECT  7.009 54.288 7.525 54.504 ;
     RECT  7.285 68.88 7.585 69.576 ;
     RECT  7.285 70.656 7.585 73.608 ;
     RECT  6.037 0.528 7.621 0.552 ;
     RECT  7.513 48.96 7.669 49.608 ;
     RECT  7.34 1.728 7.808 9.768 ;
     RECT  7.669 10.896 7.808 10.92 ;
     RECT  7.477 11.952 7.808 13.416 ;
     RECT  6.473 15.216 7.808 16.008 ;
     RECT  6.473 18.144 7.808 19.416 ;
     RECT  6.649 20.544 7.808 21.096 ;
     RECT  6.515 22.176 7.808 22.2 ;
     RECT  6.545 23.568 7.808 24.456 ;
     RECT  6.653 25.536 7.808 25.992 ;
     RECT  7.429 27.312 7.808 28.632 ;
     RECT  6.761 30.576 7.808 32.76 ;
     RECT  6.275 33.792 7.808 33.816 ;
     RECT  5.861 35.424 7.808 35.736 ;
     RECT  7.189 36.816 7.808 37.416 ;
     RECT  7.244 38.544 7.808 40.968 ;
     RECT  6.797 42.768 7.808 43.128 ;
     RECT  7.441 45.024 7.808 45.192 ;
     RECT  6.937 46.608 7.808 47.064 ;
     RECT  7.669 48.48 7.808 49.608 ;
     RECT  7.525 52.992 7.808 54.504 ;
     RECT  7.477 58.128 7.808 58.152 ;
     RECT  6.901 61.2 7.808 61.56 ;
     RECT  6.469 64.32 7.808 64.392 ;
     RECT  7.477 66 7.808 67.656 ;
     RECT  7.585 68.88 7.808 73.608 ;
     RECT  7.235 75.264 7.808 75.864 ;
     RECT  7.621 77.568 7.811 77.592 ;
     RECT  7.808 1.728 8.003 75.864 ;
     RECT  8.003 1.728 8.104 75.816 ;
     RECT  8.104 72.912 8.165 75.816 ;
     RECT  8.104 69.504 8.201 71.064 ;
     RECT  8.104 52.464 8.273 53.016 ;
     RECT  7.621 0.144 8.291 0.552 ;
     RECT  8.165 72.912 8.345 72.936 ;
     RECT  8.104 30.816 8.417 34.248 ;
     RECT  8.104 49.008 8.531 49.512 ;
     RECT  8.104 41.568 8.579 43.128 ;
     RECT  8.104 1.728 8.597 6.84 ;
     RECT  8.579 42.528 8.597 43.128 ;
     RECT  8.531 49.008 8.597 49.224 ;
     RECT  8.201 70.656 8.627 71.064 ;
     RECT  8.725 77.376 8.773 77.4 ;
     RECT  8.201 69.504 8.777 69.624 ;
     RECT  8.773 77.376 8.809 77.496 ;
     RECT  8.104 44.976 8.849 45.192 ;
     RECT  8.291 0.144 8.867 0.408 ;
     RECT  8.867 0.144 8.917 0.312 ;
     RECT  8.917 0.096 8.957 0.312 ;
     RECT  8.104 17.088 8.957 17.112 ;
     RECT  8.627 70.656 8.957 70.68 ;
     RECT  8.957 0.096 8.963 0.216 ;
     RECT  8.104 7.92 8.963 11.688 ;
     RECT  8.104 63.216 8.963 63.24 ;
     RECT  8.963 0.096 9.001 0.12 ;
     RECT  8.104 13.056 9.065 15.24 ;
     RECT  8.963 8.448 9.097 11.688 ;
     RECT  9.065 13.056 9.097 15 ;
     RECT  8.104 38.784 9.101 38.808 ;
     RECT  8.417 30.864 9.155 34.248 ;
     RECT  8.104 39.888 9.169 39.912 ;
     RECT  8.104 46.608 9.169 47.592 ;
     RECT  9.155 31.872 9.203 34.248 ;
     RECT  8.104 65.568 9.212 66.168 ;
     RECT  8.104 20.352 9.241 27.672 ;
     RECT  9.169 29.04 9.241 29.064 ;
     RECT  9.203 32.736 9.245 34.248 ;
     RECT  9.212 65.568 9.299 66.648 ;
     RECT  8.104 54.192 9.313 54.216 ;
     RECT  9.313 54.144 9.349 54.216 ;
     RECT  8.104 18.72 9.421 18.84 ;
     RECT  9.299 65.568 9.425 66.168 ;
     RECT  9.421 18.72 9.445 19.368 ;
     RECT  9.241 20.352 9.445 29.064 ;
     RECT  8.104 35.424 9.445 35.448 ;
     RECT  9.445 18.72 9.457 29.064 ;
     RECT  8.809 77.376 9.485 77.64 ;
     RECT  9.485 77.28 9.493 77.64 ;
     RECT  9.169 39.888 9.497 40.824 ;
     RECT  9.245 34.08 9.565 34.248 ;
     RECT  9.445 35.328 9.565 35.448 ;
     RECT  8.104 36.816 9.601 36.84 ;
     RECT  8.165 73.92 9.601 75.816 ;
     RECT  8.597 6.816 9.637 6.84 ;
     RECT  9.497 39.888 9.637 39.912 ;
     RECT  9.205 56.64 9.709 56.664 ;
     RECT  8.104 58.128 9.709 58.152 ;
     RECT  9.493 77.04 9.709 77.64 ;
     RECT  8.104 67.632 9.745 67.656 ;
     RECT  9.253 68.976 9.745 69 ;
     RECT  9.205 71.904 9.745 71.928 ;
     RECT  9.601 72.96 9.745 75.816 ;
     RECT  8.597 42.528 9.853 43.08 ;
     RECT  8.597 1.728 9.884 5.688 ;
     RECT  9.637 6.816 9.884 7.416 ;
     RECT  8.849 44.976 9.889 45 ;
     RECT  9.709 76.944 9.923 77.64 ;
     RECT  9.889 44.976 9.925 45.48 ;
     RECT  9.169 46.608 9.925 48.552 ;
     RECT  9.884 1.728 9.973 7.416 ;
     RECT  9.097 8.448 9.973 15 ;
     RECT  9.155 30.864 9.997 30.888 ;
     RECT  9.565 34.08 9.997 35.448 ;
     RECT  9.601 36.816 9.997 36.888 ;
     RECT  9.133 16.224 10.105 16.632 ;
     RECT  9.745 67.632 10.213 69 ;
     RECT  9.589 70.128 10.213 70.152 ;
     RECT  10.105 15.984 10.249 16.632 ;
     RECT  9.457 17.904 10.249 29.064 ;
     RECT  9.997 30.768 10.249 30.888 ;
     RECT  8.273 52.464 10.249 52.488 ;
     RECT  10.249 15.984 10.309 30.888 ;
     RECT  9.925 44.976 10.309 48.552 ;
     RECT  9.709 56.64 10.349 58.152 ;
     RECT  9.997 34.08 10.357 36.888 ;
     RECT  9.997 38.208 10.357 38.232 ;
     RECT  10.309 44.976 10.357 49.032 ;
     RECT  9.973 1.728 10.508 15 ;
     RECT  10.309 15.984 10.508 31.752 ;
     RECT  10.357 34.08 10.508 38.232 ;
     RECT  9.637 39.744 10.508 39.912 ;
     RECT  10.249 41.376 10.508 41.4 ;
     RECT  9.853 42.528 10.508 43.128 ;
     RECT  10.357 44.448 10.508 49.032 ;
     RECT  10.249 51.744 10.508 52.488 ;
     RECT  9.349 54.144 10.508 54.6 ;
     RECT  10.349 55.872 10.508 58.152 ;
     RECT  10.213 59.76 10.508 59.784 ;
     RECT  8.104 61.2 10.508 61.224 ;
     RECT  10.213 63.6 10.508 63.624 ;
     RECT  9.425 65.568 10.508 66.072 ;
     RECT  10.213 67.632 10.508 70.824 ;
     RECT  9.745 71.904 10.508 75.816 ;
     RECT  10.508 1.728 10.804 75.816 ;
     RECT  10.804 1.728 10.892 1.896 ;
     RECT  10.804 65.52 10.931 66.168 ;
     RECT  9.923 77.52 10.933 77.64 ;
     RECT  10.804 51.744 10.973 54.696 ;
     RECT  10.892 1.104 10.979 1.896 ;
     RECT  10.804 23.136 10.979 29.112 ;
     RECT  10.804 39.744 10.979 45.48 ;
     RECT  10.973 51.744 10.979 51.912 ;
     RECT  10.804 10.704 11.017 19.464 ;
     RECT  10.933 77.424 11.029 77.64 ;
     RECT  10.804 20.832 11.045 21.144 ;
     RECT  10.804 69.456 11.081 70.824 ;
     RECT  10.979 23.136 11.117 23.592 ;
     RECT  10.973 53.04 11.117 54.696 ;
     RECT  10.804 47.712 11.153 47.88 ;
     RECT  10.804 57.024 11.164 57.816 ;
     RECT  10.979 26.496 11.189 29.112 ;
     RECT  10.979 39.744 11.233 44.664 ;
     RECT  11.045 20.832 11.315 20.904 ;
     RECT  11.081 69.456 11.356 70.68 ;
     RECT  10.804 67.632 11.363 68.376 ;
     RECT  11.017 10.704 11.377 18.216 ;
     RECT  11.356 69.456 11.377 70.152 ;
     RECT  11.377 10.704 11.405 17.064 ;
     RECT  10.979 24.72 11.405 25.08 ;
     RECT  10.804 34.224 11.411 37.416 ;
     RECT  10.804 49.008 11.411 50.76 ;
     RECT  11.405 10.704 11.441 15 ;
     RECT  10.804 38.688 11.441 38.712 ;
     RECT  10.804 63.264 11.441 63.768 ;
     RECT  11.189 26.496 11.477 27.96 ;
     RECT  11.411 49.008 11.485 49.56 ;
     RECT  11.411 34.224 11.513 35.88 ;
     RECT  11.405 24.72 11.549 25.032 ;
     RECT  11.477 26.496 11.549 27.72 ;
     RECT  10.931 65.568 11.549 66.168 ;
     RECT  11.315 20.832 11.585 20.856 ;
     RECT  11.405 15.984 11.593 17.064 ;
     RECT  11.411 50.736 11.621 50.76 ;
     RECT  11.549 24.96 11.657 25.032 ;
     RECT  11.441 10.704 11.693 14.952 ;
     RECT  11.657 24.96 11.765 24.984 ;
     RECT  11.441 63.648 11.795 63.768 ;
     RECT  10.804 7.344 11.797 9.048 ;
     RECT  11.233 39.744 11.837 41.592 ;
     RECT  11.485 49.248 11.837 49.56 ;
     RECT  11.797 7.344 11.843 9.384 ;
     RECT  10.804 71.904 11.9 72.936 ;
     RECT  11.693 10.992 11.909 14.952 ;
     RECT  10.979 51.888 11.909 51.912 ;
     RECT  11.9 71.76 11.941 72.936 ;
     RECT  11.377 69.456 11.945 70.104 ;
     RECT  11.233 42.576 11.977 44.664 ;
     RECT  11.941 71.76 11.987 73.224 ;
     RECT  11.977 42.576 11.989 44.952 ;
     RECT  10.804 32.976 12.013 33 ;
     RECT  11.513 34.224 12.013 35.448 ;
     RECT  10.804 2.88 12.017 5.688 ;
     RECT  11.843 7.344 12.017 8.088 ;
     RECT  11.549 65.952 12.053 66.168 ;
     RECT  11.363 68.352 12.053 68.376 ;
     RECT  11.989 42.576 12.076 45.048 ;
     RECT  10.165 0.096 12.085 0.12 ;
     RECT  11.411 37.392 12.089 37.416 ;
     RECT  11.164 57.024 12.089 57.336 ;
     RECT  12.076 42.72 12.121 45.048 ;
     RECT  10.979 1.728 12.133 1.896 ;
     RECT  12.017 2.88 12.133 3.864 ;
     RECT  12.121 42.72 12.157 45.576 ;
     RECT  12.049 46.608 12.157 46.632 ;
     RECT  12.133 1.728 12.161 3.864 ;
     RECT  11.909 10.992 12.161 13.656 ;
     RECT  12.161 3.84 12.179 3.864 ;
     RECT  12.017 4.848 12.179 5.688 ;
     RECT  12.085 0.096 12.181 0.168 ;
     RECT  12.089 57.312 12.197 57.336 ;
     RECT  11.837 40.032 12.22 41.592 ;
     RECT  10.804 30.432 12.265 30.456 ;
     RECT  10.804 31.728 12.265 31.8 ;
     RECT  10.804 75.264 12.265 75.816 ;
     RECT  12.181 0.096 12.269 0.216 ;
     RECT  11.117 53.568 12.337 54.696 ;
     RECT  11.029 77.376 12.341 77.64 ;
     RECT  12.265 75.264 12.373 75.864 ;
     RECT  12.157 42.72 12.38 46.632 ;
     RECT  11.153 47.856 12.401 47.88 ;
     RECT  12.341 77.376 12.413 77.544 ;
     RECT  12.337 53.376 12.445 54.696 ;
     RECT  10.804 60.816 12.445 60.84 ;
     RECT  12.373 74.592 12.469 75.864 ;
     RECT  11.117 23.568 12.481 23.592 ;
     RECT  11.893 62.64 12.481 62.664 ;
     RECT  11.593 16.56 12.517 17.064 ;
     RECT  11.377 18.192 12.517 18.216 ;
     RECT  11.017 19.44 12.517 19.464 ;
     RECT  12.445 20.976 12.553 21 ;
     RECT  12.053 65.952 12.553 65.976 ;
     RECT  12.481 59.184 12.589 59.208 ;
     RECT  12.517 19.2 12.661 19.464 ;
     RECT  12.589 58.992 12.661 59.208 ;
     RECT  11.987 72.912 12.661 73.224 ;
     RECT  12.269 0.144 12.665 0.216 ;
     RECT  12.413 77.472 12.665 77.544 ;
     RECT  12.661 19.2 12.697 19.992 ;
     RECT  12.553 20.976 12.697 21.432 ;
     RECT  12.38 42.72 12.733 46.68 ;
     RECT  12.517 16.56 12.769 18.216 ;
     RECT  12.697 19.2 12.769 21.432 ;
     RECT  12.013 32.976 12.769 35.448 ;
     RECT  11.837 49.248 12.769 49.272 ;
     RECT  12.769 16.56 12.805 21.432 ;
     RECT  12.733 42.72 12.805 46.728 ;
     RECT  12.401 47.856 12.805 47.928 ;
     RECT  11.189 28.944 12.815 29.112 ;
     RECT  12.265 30.432 12.815 31.8 ;
     RECT  11.945 69.456 12.841 69.48 ;
     RECT  11.549 27.696 12.853 27.72 ;
     RECT  12.625 38.688 12.877 38.712 ;
     RECT  12.481 62.256 12.877 62.664 ;
     RECT  11.795 63.744 12.877 63.768 ;
     RECT  12.553 64.992 12.877 65.976 ;
     RECT  12.815 28.944 12.913 31.8 ;
     RECT  12.769 32.976 12.913 36.36 ;
     RECT  12.661 58.656 12.913 59.208 ;
     RECT  12.877 38.16 12.949 38.712 ;
     RECT  11.987 71.904 12.985 71.928 ;
     RECT  12.661 72.912 12.985 73.56 ;
     RECT  11.909 14.736 12.997 14.952 ;
     RECT  12.481 23.376 13.013 23.592 ;
     RECT  12.985 71.904 13.021 73.56 ;
     RECT  12.469 74.592 13.021 76.392 ;
     RECT  12.179 4.848 13.045 5.304 ;
     RECT  12.445 52.416 13.045 54.696 ;
     RECT  12.805 6.72 13.057 6.744 ;
     RECT  11.843 9.36 13.057 9.384 ;
     RECT  12.161 10.992 13.057 13.032 ;
     RECT  12.769 48.96 13.057 49.272 ;
     RECT  13.057 9.36 13.093 9.624 ;
     RECT  13.057 10.704 13.093 13.032 ;
     RECT  12.949 38.16 13.093 38.76 ;
     RECT  12.22 40.032 13.093 40.056 ;
     RECT  13.045 52.416 13.093 55.416 ;
     RECT  13.057 56.592 13.093 56.616 ;
     RECT  12.913 58.656 13.093 59.304 ;
     RECT  12.445 60.384 13.093 60.84 ;
     RECT  13.021 71.904 13.097 76.392 ;
     RECT  12.997 14.544 13.129 14.952 ;
     RECT  12.805 16.56 13.129 21.528 ;
     RECT  12.625 51.216 13.129 51.24 ;
     RECT  12.949 67.296 13.165 67.32 ;
     RECT  12.161 1.728 13.208 2.28 ;
     RECT  13.045 3.888 13.208 5.304 ;
     RECT  13.057 6.624 13.208 6.744 ;
     RECT  12.017 7.872 13.208 8.088 ;
     RECT  13.093 9.36 13.208 13.032 ;
     RECT  13.129 14.544 13.208 21.528 ;
     RECT  13.013 23.376 13.208 24.312 ;
     RECT  11.549 26.496 13.208 26.52 ;
     RECT  12.853 27.696 13.208 27.912 ;
     RECT  12.913 28.944 13.208 36.36 ;
     RECT  13.093 38.16 13.208 40.056 ;
     RECT  12.22 41.136 13.208 41.592 ;
     RECT  12.805 42.72 13.208 47.928 ;
     RECT  13.057 48.96 13.208 49.32 ;
     RECT  13.129 50.928 13.208 51.24 ;
     RECT  13.093 52.416 13.208 56.616 ;
     RECT  13.093 58.656 13.208 61.176 ;
     RECT  12.877 62.256 13.208 65.976 ;
     RECT  13.165 67.296 13.208 67.656 ;
     RECT  12.841 69.024 13.208 69.48 ;
     RECT  13.097 71.904 13.208 75.612 ;
     RECT  13.208 1.728 13.312 75.612 ;
     RECT  13.312 1.728 13.504 75.342 ;
     RECT  13.504 63.456 13.565 73.272 ;
     RECT  13.504 7.92 13.619 10.824 ;
     RECT  13.504 30.768 13.619 41.16 ;
     RECT  13.504 50.544 13.619 56.808 ;
     RECT  13.565 65.328 13.619 73.272 ;
     RECT  13.619 39.84 13.66 40.536 ;
     RECT  13.619 65.328 13.66 71.256 ;
     RECT  13.619 52.992 13.667 56.808 ;
     RECT  13.619 9.36 13.673 10.824 ;
     RECT  13.504 58.128 13.708 59.88 ;
     RECT  12.665 0.144 13.709 0.168 ;
     RECT  13.673 9.36 13.709 9.576 ;
     RECT  13.708 58.128 13.709 58.824 ;
     RECT  13.504 25.728 13.715 25.752 ;
     RECT  13.673 10.8 13.745 10.824 ;
     RECT  13.504 1.728 13.781 2.616 ;
     RECT  13.619 30.768 13.781 38.856 ;
     RECT  13.565 63.456 13.781 64.2 ;
     RECT  12.665 77.52 13.781 77.544 ;
     RECT  13.667 52.992 13.811 53.112 ;
     RECT  13.667 54.336 13.811 56.808 ;
     RECT  13.504 14.736 13.817 14.76 ;
     RECT  13.781 63.456 13.853 63.48 ;
     RECT  13.504 18.816 13.889 18.84 ;
     RECT  13.781 30.768 13.925 34.248 ;
     RECT  13.504 28.944 13.955 29.64 ;
     RECT  13.504 20.976 13.997 21.72 ;
     RECT  13.781 1.776 14.033 2.616 ;
     RECT  13.955 29.04 14.033 29.64 ;
     RECT  13.781 35.232 14.105 38.856 ;
     RECT  13.504 42.144 14.149 49.32 ;
     RECT  13.504 15.744 14.213 17.112 ;
     RECT  13.66 39.84 14.213 40.104 ;
     RECT  13.66 65.328 14.213 67.896 ;
     RECT  14.105 35.232 14.249 38.52 ;
     RECT  13.925 30.768 14.284 33.24 ;
     RECT  14.213 15.744 14.285 16.584 ;
     RECT  14.249 35.232 14.285 37.176 ;
     RECT  14.033 29.04 14.321 29.592 ;
     RECT  13.925 34.224 14.465 34.248 ;
     RECT  14.213 65.328 14.483 65.592 ;
     RECT  13.619 72.288 14.497 73.272 ;
     RECT  13.504 74.304 14.497 75.144 ;
     RECT  13.66 68.976 14.501 71.256 ;
     RECT  14.149 42.192 14.533 49.32 ;
     RECT  14.483 65.472 14.573 65.592 ;
     RECT  13.811 52.992 14.605 53.064 ;
     RECT  13.504 4.08 14.641 6.264 ;
     RECT  13.997 21.12 14.645 21.72 ;
     RECT  14.497 72.288 14.645 75.144 ;
     RECT  13.709 58.416 14.677 58.824 ;
     RECT  14.645 21.12 14.681 21.624 ;
     RECT  14.501 69.552 14.753 71.256 ;
     RECT  13.504 12.48 14.785 12.504 ;
     RECT  14.533 42.192 14.785 49.512 ;
     RECT  13.619 50.544 14.785 51.336 ;
     RECT  13.811 54.336 14.785 56.712 ;
     RECT  14.284 30.768 14.819 33.096 ;
     RECT  14.645 72.432 14.819 75.144 ;
     RECT  13.504 26.736 14.857 27.336 ;
     RECT  14.681 21.504 14.861 21.624 ;
     RECT  14.677 58.032 14.869 58.824 ;
     RECT  13.708 59.856 14.869 59.88 ;
     RECT  14.605 52.848 14.876 53.064 ;
     RECT  14.876 52.464 14.924 53.064 ;
     RECT  14.785 54.336 14.924 56.952 ;
     RECT  14.785 12.48 14.929 12.792 ;
     RECT  14.819 30.768 14.933 32.808 ;
     RECT  13.709 9.552 14.965 9.576 ;
     RECT  14.749 10.8 14.965 10.824 ;
     RECT  14.933 30.768 14.965 32.52 ;
     RECT  14.213 40.08 14.965 40.104 ;
     RECT  14.785 42.192 14.965 51.336 ;
     RECT  14.924 52.464 14.965 56.952 ;
     RECT  14.033 2.592 15.164 2.616 ;
     RECT  14.641 3.888 15.164 6.264 ;
     RECT  15.164 2.592 15.205 6.264 ;
     RECT  14.321 29.232 15.253 29.592 ;
     RECT  14.965 30.576 15.253 32.52 ;
     RECT  14.965 42.192 15.253 56.952 ;
     RECT  14.869 58.032 15.253 59.88 ;
     RECT  14.573 65.568 15.253 65.592 ;
     RECT  14.213 66.576 15.253 67.896 ;
     RECT  14.929 12.48 15.301 13.032 ;
     RECT  14.821 14.256 15.301 14.28 ;
     RECT  15.301 12.48 15.349 14.28 ;
     RECT  15.205 2.592 15.361 6.936 ;
     RECT  13.504 61.056 15.397 61.656 ;
     RECT  13.619 7.92 15.433 7.944 ;
     RECT  14.965 40.08 15.452 40.584 ;
     RECT  14.965 9.552 15.469 10.824 ;
     RECT  14.249 38.448 15.493 38.472 ;
     RECT  15.452 39.456 15.493 40.584 ;
     RECT  15.397 61.056 15.5 61.944 ;
     RECT  13.504 22.752 15.505 23.592 ;
     RECT  15.253 65.568 15.541 67.896 ;
     RECT  14.285 16.56 15.577 16.584 ;
     RECT  15.541 64.944 15.577 67.896 ;
     RECT  15.493 38.448 15.596 40.584 ;
     RECT  15.5 61.056 15.605 62.04 ;
     RECT  15.048 63.072 15.605 63.096 ;
     RECT  15.469 9.552 15.637 11.16 ;
     RECT  15.349 12.48 15.637 14.472 ;
     RECT  15.361 2.304 15.649 6.936 ;
     RECT  15.433 7.92 15.649 7.992 ;
     RECT  15.577 64.224 15.649 67.896 ;
     RECT  15.253 29.232 15.685 32.52 ;
     RECT  15.757 34.08 15.793 34.104 ;
     RECT  15.605 61.056 15.793 63.096 ;
     RECT  15.649 64.224 15.793 67.944 ;
     RECT  15.649 2.304 15.908 7.992 ;
     RECT  15.637 9.552 15.908 14.472 ;
     RECT  15.577 16.56 15.908 17.112 ;
     RECT  14.641 20.064 15.908 20.088 ;
     RECT  14.861 21.504 15.908 21.528 ;
     RECT  15.505 22.752 15.908 24.216 ;
     RECT  15.721 25.536 15.908 25.56 ;
     RECT  14.857 26.64 15.908 27.336 ;
     RECT  15.685 28.944 15.908 32.52 ;
     RECT  15.793 33.6 15.908 34.104 ;
     RECT  14.285 35.712 15.908 37.176 ;
     RECT  15.596 38.16 15.908 40.584 ;
     RECT  15.253 41.664 15.908 59.88 ;
     RECT  15.793 61.056 15.908 67.944 ;
     RECT  14.753 69.552 15.908 70.728 ;
     RECT  14.819 72.432 15.908 75.048 ;
     RECT  15.908 2.148 16.012 75.612 ;
     RECT  16.012 2.304 16.204 75.342 ;
     RECT  16.204 25.536 16.301 26.712 ;
     RECT  16.204 71.808 16.301 74.952 ;
     RECT  16.204 10.176 16.373 11.16 ;
     RECT  16.204 66.576 16.444 67.944 ;
     RECT  16.444 66.576 16.451 66.792 ;
     RECT  16.204 3.408 16.481 3.432 ;
     RECT  16.204 8.592 16.481 9.192 ;
     RECT  16.204 28.944 16.481 29.256 ;
     RECT  16.481 8.688 16.499 9.192 ;
     RECT  16.204 68.976 16.499 70.728 ;
     RECT  16.499 68.976 16.54 70.296 ;
     RECT  16.204 35.328 16.547 63.864 ;
     RECT  16.301 71.808 16.547 74.712 ;
     RECT  16.204 2.304 16.553 2.328 ;
     RECT  16.547 73.872 16.553 74.712 ;
     RECT  16.547 35.328 16.589 62.136 ;
     RECT  16.547 63.264 16.595 63.864 ;
     RECT  16.499 9.12 16.625 9.192 ;
     RECT  16.451 66.576 16.625 66.6 ;
     RECT  16.54 69.36 16.625 70.296 ;
     RECT  16.204 22.512 16.661 24.216 ;
     RECT  16.595 63.264 16.691 63.816 ;
     RECT  16.204 6.816 16.733 7.416 ;
     RECT  16.553 74.592 16.733 74.712 ;
     RECT  16.547 71.808 16.739 72.456 ;
     RECT  16.301 25.68 16.769 26.712 ;
     RECT  16.625 9.12 16.805 9.144 ;
     RECT  16.204 12.384 16.805 12.504 ;
     RECT  16.204 31.728 16.805 34.104 ;
     RECT  16.204 16.56 16.913 17.112 ;
     RECT  16.204 64.944 16.913 65.016 ;
     RECT  16.769 25.68 16.949 26.664 ;
     RECT  16.691 63.264 16.985 63.288 ;
     RECT  16.805 12.48 17.021 12.504 ;
     RECT  16.661 22.512 17.021 23.592 ;
     RECT  16.589 40.8 17.021 59.112 ;
     RECT  16.589 60.192 17.021 62.136 ;
     RECT  16.625 70.272 17.057 70.296 ;
     RECT  17.021 40.8 17.093 47.448 ;
     RECT  17.021 48.432 17.093 59.112 ;
     RECT  17.093 50.352 17.123 59.112 ;
     RECT  16.913 16.56 17.129 16.584 ;
     RECT  16.589 35.328 17.129 39 ;
     RECT  17.123 50.352 17.129 51.816 ;
     RECT  17.123 53.088 17.165 59.112 ;
     RECT  17.165 53.376 17.171 59.112 ;
     RECT  17.093 46.752 17.201 47.448 ;
     RECT  16.913 64.944 17.219 64.968 ;
     RECT  16.805 31.728 17.237 34.008 ;
     RECT  17.201 46.752 17.237 47.4 ;
     RECT  17.237 46.992 17.267 47.4 ;
     RECT  16.204 30.432 17.269 30.6 ;
     RECT  17.237 31.728 17.269 32.376 ;
     RECT  17.021 60.192 17.273 61.32 ;
     RECT  16.204 21.504 17.305 21.528 ;
     RECT  16.949 25.68 17.305 25.704 ;
     RECT  17.129 36.912 17.315 39 ;
     RECT  16.444 67.92 17.315 67.944 ;
     RECT  16.204 13.536 17.341 15.384 ;
     RECT  16.739 71.808 17.345 71.832 ;
     RECT  17.093 48.432 17.363 49.368 ;
     RECT  16.481 29.232 17.377 29.256 ;
     RECT  17.269 30.432 17.377 32.376 ;
     RECT  16.733 74.592 17.381 74.616 ;
     RECT  16.204 18.144 17.413 18.168 ;
     RECT  17.093 40.8 17.453 45.576 ;
     RECT  17.171 54.144 17.453 59.112 ;
     RECT  17.453 54.672 17.593 59.112 ;
     RECT  17.453 40.8 17.629 45.528 ;
     RECT  17.305 25.104 17.633 25.704 ;
     RECT  17.021 23.136 17.653 23.592 ;
     RECT  17.341 12.624 17.953 15.384 ;
     RECT  17.948 10.848 17.989 10.872 ;
     RECT  17.953 12.624 17.989 16.056 ;
     RECT  16.204 5.28 18.133 5.304 ;
     RECT  17.989 10.848 18.133 16.056 ;
     RECT  17.315 36.912 18.181 37.08 ;
     RECT  18.241 65.232 18.277 65.256 ;
     RECT  16.733 6.912 18.349 7.416 ;
     RECT  17.267 47.136 18.349 47.4 ;
     RECT  18.277 64.992 18.349 65.352 ;
     RECT  18.373 66.72 18.383 66.744 ;
     RECT  18.383 66.72 18.385 67.32 ;
     RECT  18.349 47.136 18.421 47.448 ;
     RECT  17.557 69.024 18.421 69.048 ;
     RECT  18.277 61.92 18.469 61.944 ;
     RECT  18.349 64.656 18.469 65.352 ;
     RECT  17.129 35.328 18.601 35.88 ;
     RECT  18.181 36.864 18.601 37.08 ;
     RECT  17.809 3.408 18.608 3.432 ;
     RECT  18.133 4.512 18.608 5.304 ;
     RECT  18.349 6.912 18.608 8.184 ;
     RECT  18.133 10.224 18.608 16.056 ;
     RECT  17.413 18.144 18.608 18.984 ;
     RECT  17.305 21.264 18.608 21.528 ;
     RECT  17.653 23.136 18.608 23.88 ;
     RECT  17.633 25.104 18.608 25.128 ;
     RECT  17.917 26.208 18.608 26.232 ;
     RECT  17.377 29.232 18.608 32.376 ;
     RECT  17.237 33.552 18.608 34.008 ;
     RECT  18.601 35.328 18.608 37.08 ;
     RECT  17.315 38.208 18.608 39 ;
     RECT  17.629 40.032 18.608 45.528 ;
     RECT  18.421 46.8 18.608 47.448 ;
     RECT  17.363 48.432 18.608 49.32 ;
     RECT  17.129 50.544 18.608 51.48 ;
     RECT  17.593 54.672 18.608 59.16 ;
     RECT  17.273 60.528 18.608 60.552 ;
     RECT  18.469 61.728 18.608 61.944 ;
     RECT  18.469 63.792 18.608 65.352 ;
     RECT  18.385 66.72 18.608 67.896 ;
     RECT  18.421 69.024 18.608 69.816 ;
     RECT  18.493 73.824 18.608 73.848 ;
     RECT  18.608 2.148 18.712 75.612 ;
     RECT  18.712 2.418 18.904 75.342 ;
     RECT  18.904 33.552 18.965 33.576 ;
     RECT  18.904 60.192 19.001 65.256 ;
     RECT  18.904 50.688 19.037 52.824 ;
     RECT  18.904 4.32 19.043 6.84 ;
     RECT  18.904 35.856 19.043 36.936 ;
     RECT  18.904 53.904 19.043 55.512 ;
     RECT  19.037 51.888 19.073 52.824 ;
     RECT  19.043 35.856 19.081 36.888 ;
     RECT  18.904 25.536 19.091 27.336 ;
     RECT  18.904 41.424 19.091 45.72 ;
     RECT  18.904 11.52 19.109 11.736 ;
     RECT  18.904 13.056 19.181 14.472 ;
     RECT  19.043 54.336 19.181 55.512 ;
     RECT  18.904 38.4 19.187 40.056 ;
     RECT  18.904 2.832 19.217 2.856 ;
     RECT  18.904 67.296 19.253 67.416 ;
     RECT  18.904 18.24 19.289 18.792 ;
     RECT  19.091 42.192 19.289 45.72 ;
     RECT  18.904 68.976 19.289 70.872 ;
     RECT  19.289 42.192 19.331 45.576 ;
     RECT  19.001 60.192 19.361 63.24 ;
     RECT  19.187 40.032 19.505 40.056 ;
     RECT  19.001 64.656 19.523 65.256 ;
     RECT  19.289 18.24 19.541 18.264 ;
     RECT  19.081 36.48 19.541 36.888 ;
     RECT  19.331 42.192 19.541 45.528 ;
     RECT  19.541 36.48 19.613 36.504 ;
     RECT  19.523 64.656 19.649 64.968 ;
     RECT  19.289 69.984 19.649 70.872 ;
     RECT  19.043 4.56 19.685 6.84 ;
     RECT  18.904 29.04 19.715 32.376 ;
     RECT  19.715 29.04 19.757 30.792 ;
     RECT  19.649 64.656 19.793 64.68 ;
     RECT  18.904 10.08 19.868 10.536 ;
     RECT  18.904 46.752 19.897 47.4 ;
     RECT  18.904 48.672 19.897 49.32 ;
     RECT  19.868 9.936 19.909 10.536 ;
     RECT  19.109 11.52 19.909 11.544 ;
     RECT  19.685 4.656 19.933 6.84 ;
     RECT  19.909 9.936 19.955 11.544 ;
     RECT  19.181 13.44 19.969 14.472 ;
     RECT  19.964 16.512 20.005 16.536 ;
     RECT  19.253 67.296 20.005 67.32 ;
     RECT  19.933 4.656 20.045 7.704 ;
     RECT  20.005 16.512 20.051 16.968 ;
     RECT  19.091 26.448 20.077 27.336 ;
     RECT  18.904 73.584 20.113 74.616 ;
     RECT  19.897 46.752 20.189 49.32 ;
     RECT  19.073 51.888 20.189 51.912 ;
     RECT  19.969 13.44 20.195 15.336 ;
     RECT  19.037 50.688 20.197 50.856 ;
     RECT  19.361 60.192 20.225 62.808 ;
     RECT  20.113 73.248 20.225 74.616 ;
     RECT  20.195 14.544 20.236 14.76 ;
     RECT  20.197 49.488 20.243 50.856 ;
     RECT  18.904 21.6 20.257 23.592 ;
     RECT  19.757 29.04 20.261 29.88 ;
     RECT  19.955 10.08 20.329 11.544 ;
     RECT  18.904 57.168 20.329 57.192 ;
     RECT  19.715 31.92 20.365 32.376 ;
     RECT  19.541 42.288 20.401 45.528 ;
     RECT  20.189 46.752 20.401 48.456 ;
     RECT  18.904 8.832 20.492 8.856 ;
     RECT  19.187 38.4 20.54 38.52 ;
     RECT  20.005 66.816 20.54 67.32 ;
     RECT  18.904 19.92 20.545 20.616 ;
     RECT  20.257 21.6 20.545 24.12 ;
     RECT  19.289 68.976 20.581 69 ;
     RECT  19.649 69.984 20.684 70.584 ;
     RECT  20.581 68.352 20.689 69 ;
     RECT  20.684 69.984 20.689 70.728 ;
     RECT  20.545 72 20.689 72.024 ;
     RECT  20.689 68.352 20.725 72.216 ;
     RECT  20.225 73.248 20.725 74.136 ;
     RECT  20.077 25.632 20.797 27.336 ;
     RECT  20.54 37.584 20.833 38.52 ;
     RECT  20.225 60.192 20.905 61.944 ;
     RECT  20.545 19.92 20.941 24.12 ;
     RECT  20.54 66.72 20.941 67.32 ;
     RECT  20.725 68.352 20.941 74.136 ;
     RECT  20.045 4.656 20.977 6.84 ;
     RECT  20.492 7.872 20.977 8.856 ;
     RECT  20.329 10.08 20.977 12.312 ;
     RECT  20.977 7.872 21.013 12.312 ;
     RECT  20.195 13.44 21.013 13.464 ;
     RECT  20.261 29.856 21.049 29.88 ;
     RECT  20.977 3.936 21.109 6.84 ;
     RECT  21.013 7.872 21.109 13.464 ;
     RECT  20.113 35.424 21.109 35.448 ;
     RECT  19.181 54.336 21.109 54.36 ;
     RECT  19.181 55.488 21.109 55.512 ;
     RECT  20.329 56.832 21.109 57.192 ;
     RECT  20.437 58.896 21.109 58.92 ;
     RECT  20.905 60.144 21.109 61.944 ;
     RECT  21.109 56.832 21.116 57.624 ;
     RECT  20.941 63.264 21.121 64.2 ;
     RECT  20.236 14.736 21.157 14.76 ;
     RECT  20.365 31.92 21.157 32.472 ;
     RECT  20.833 36.528 21.157 38.52 ;
     RECT  21.157 14.736 21.229 14.808 ;
     RECT  21.193 41.136 21.265 41.16 ;
     RECT  21.265 40.56 21.301 41.16 ;
     RECT  21.109 3.936 21.308 13.464 ;
     RECT  21.229 14.736 21.308 15.048 ;
     RECT  20.051 16.944 21.308 16.968 ;
     RECT  21.049 18.048 21.308 18.072 ;
     RECT  20.941 19.056 21.308 24.12 ;
     RECT  20.797 25.632 21.308 27.912 ;
     RECT  21.049 29.856 21.308 30.12 ;
     RECT  21.157 31.776 21.308 32.472 ;
     RECT  20.221 33.504 21.308 33.528 ;
     RECT  21.109 34.56 21.308 35.448 ;
     RECT  21.157 36.528 21.308 39.096 ;
     RECT  21.301 40.32 21.308 41.16 ;
     RECT  20.401 42.288 21.308 48.456 ;
     RECT  20.243 49.488 21.308 50.04 ;
     RECT  20.545 51.072 21.308 51.72 ;
     RECT  21.157 53.088 21.308 53.112 ;
     RECT  21.109 54.336 21.308 55.512 ;
     RECT  21.116 56.832 21.308 57.72 ;
     RECT  21.109 58.896 21.308 61.944 ;
     RECT  21.121 63.264 21.308 65.064 ;
     RECT  20.941 66.72 21.308 74.136 ;
     RECT  21.308 2.148 21.509 75.612 ;
     RECT  21.509 2.148 21.541 75.816 ;
     RECT  21.541 1.728 21.593 75.816 ;
     RECT  21.593 1.728 21.604 75.342 ;
     RECT  21.604 73.296 21.629 73.656 ;
     RECT  21.604 1.728 21.665 2.856 ;
     RECT  21.629 73.344 21.701 73.656 ;
     RECT  21.604 59.76 21.773 64.392 ;
     RECT  21.604 70.656 21.773 72.12 ;
     RECT  21.604 55.392 21.779 55.512 ;
     RECT  21.773 59.76 21.779 61.704 ;
     RECT  21.604 30.096 21.809 31.944 ;
     RECT  21.604 67.008 21.809 67.848 ;
     RECT  21.701 73.632 21.809 73.656 ;
     RECT  21.604 54.096 21.82 54.12 ;
     RECT  21.604 18.192 21.845 22.872 ;
     RECT  21.604 25.728 21.845 26.664 ;
     RECT  21.773 62.784 21.875 64.392 ;
     RECT  21.773 71.28 21.917 72.12 ;
     RECT  21.809 31.92 21.953 31.944 ;
     RECT  21.809 67.824 22.019 67.848 ;
     RECT  21.604 46.224 22.133 48.456 ;
     RECT  21.875 63.168 22.133 64.392 ;
     RECT  21.779 55.488 22.163 55.512 ;
     RECT  21.604 52.992 22.169 53.016 ;
     RECT  21.604 41.712 22.205 45 ;
     RECT  21.604 14.208 22.211 15.384 ;
     RECT  21.604 36.528 22.313 36.552 ;
     RECT  22.133 46.896 22.313 48.456 ;
     RECT  21.604 69.024 22.313 69.24 ;
     RECT  21.604 38.016 22.457 40.584 ;
     RECT  22.133 63.888 22.493 64.392 ;
     RECT  21.604 24.096 22.529 24.6 ;
     RECT  21.604 51.36 22.597 52.008 ;
     RECT  21.779 59.76 22.597 59.784 ;
     RECT  21.604 11.952 22.633 12.024 ;
     RECT  21.604 56.496 22.673 58.152 ;
     RECT  21.845 18.192 22.709 22.824 ;
     RECT  21.604 10.848 22.733 10.872 ;
     RECT  22.633 11.952 22.733 12.36 ;
     RECT  22.211 14.928 22.741 15.384 ;
     RECT  21.604 27.648 22.777 27.912 ;
     RECT  21.779 61.104 22.777 61.704 ;
     RECT  21.604 5.088 22.781 9.576 ;
     RECT  22.673 56.496 22.781 57.48 ;
     RECT  22.733 10.848 22.787 12.36 ;
     RECT  21.917 72.096 22.813 72.12 ;
     RECT  22.787 11.376 22.817 12.36 ;
     RECT  22.705 45.792 22.817 45.816 ;
     RECT  22.493 64.176 22.849 64.392 ;
     RECT  22.777 27.504 22.885 27.912 ;
     RECT  22.529 24.576 22.925 24.6 ;
     RECT  22.597 51.36 22.925 52.728 ;
     RECT  22.777 61.104 22.997 62.184 ;
     RECT  22.849 64.176 23.02 64.968 ;
     RECT  22.597 59.232 23.036 59.784 ;
     RECT  23.036 59.232 23.077 59.832 ;
     RECT  22.997 61.104 23.077 61.656 ;
     RECT  22.817 11.664 23.209 12.36 ;
     RECT  22.741 14.928 23.209 17.208 ;
     RECT  22.709 18.192 23.209 22.488 ;
     RECT  21.604 35.328 23.209 35.448 ;
     RECT  21.809 30.096 23.245 30.6 ;
     RECT  21.845 25.728 23.269 26.376 ;
     RECT  23.029 13.824 23.281 13.944 ;
     RECT  23.065 68.928 23.365 68.952 ;
     RECT  23.101 70.128 23.365 70.68 ;
     RECT  21.665 2.496 23.425 2.856 ;
     RECT  22.457 38.016 23.461 40.488 ;
     RECT  21.604 49.584 23.461 49.608 ;
     RECT  23.029 54.72 23.461 54.744 ;
     RECT  22.781 5.28 23.497 9.576 ;
     RECT  23.209 11.664 23.557 12.504 ;
     RECT  23.281 13.632 23.557 13.944 ;
     RECT  23.209 14.928 23.557 22.488 ;
     RECT  22.313 46.896 23.557 46.92 ;
     RECT  22.313 48.24 23.557 48.456 ;
     RECT  23.245 30.096 23.569 30.84 ;
     RECT  23.269 25.728 23.605 26.472 ;
     RECT  23.557 46.272 23.66 48.456 ;
     RECT  23.461 49.584 23.66 50.04 ;
     RECT  22.205 41.712 23.701 44.472 ;
     RECT  23.425 2.496 23.749 3.384 ;
     RECT  23.701 41.712 23.857 44.904 ;
     RECT  23.66 46.272 23.857 50.04 ;
     RECT  23.749 2.496 23.893 4.248 ;
     RECT  23.497 5.28 23.893 10.2 ;
     RECT  23.569 29.568 23.929 30.84 ;
     RECT  23.893 2.496 24.008 10.2 ;
     RECT  23.557 11.664 24.008 22.488 ;
     RECT  23.605 25.2 24.008 26.472 ;
     RECT  22.885 27.456 24.008 27.912 ;
     RECT  23.929 29.568 24.008 31.416 ;
     RECT  23.209 35.328 24.008 36.024 ;
     RECT  23.461 37.344 24.008 40.488 ;
     RECT  23.857 41.712 24.008 50.04 ;
     RECT  22.925 51.36 24.008 52.488 ;
     RECT  23.461 53.904 24.008 54.744 ;
     RECT  22.781 57.456 24.008 57.48 ;
     RECT  23.077 59.232 24.008 61.656 ;
     RECT  23.02 64.944 24.008 64.968 ;
     RECT  23.641 66.096 24.008 66.12 ;
     RECT  23.065 67.824 24.008 67.848 ;
     RECT  23.365 68.928 24.008 70.68 ;
     RECT  22.813 72.096 24.008 73.032 ;
     RECT  21.604 74.688 24.008 74.712 ;
     RECT  24.008 2.148 24.112 75.612 ;
     RECT  24.112 2.418 24.304 75.342 ;
     RECT  24.304 24.48 24.419 28.488 ;
     RECT  24.304 31.392 24.419 31.416 ;
     RECT  24.419 24.48 24.46 27.432 ;
     RECT  24.304 51.984 24.515 53.928 ;
     RECT  24.304 74.64 24.545 74.712 ;
     RECT  24.304 2.832 24.581 22.488 ;
     RECT  24.419 28.464 24.581 28.488 ;
     RECT  24.581 2.832 24.617 7.368 ;
     RECT  24.581 8.832 24.617 22.488 ;
     RECT  24.304 37.344 24.617 39.576 ;
     RECT  24.617 8.928 24.653 22.488 ;
     RECT  24.304 60.672 24.653 62.232 ;
     RECT  24.304 29.472 24.689 30.12 ;
     RECT  24.653 60.672 24.689 61.992 ;
     RECT  24.617 3.168 24.725 7.368 ;
     RECT  24.304 40.56 24.761 45.576 ;
     RECT  24.304 46.608 24.796 48.504 ;
     RECT  24.761 40.56 24.803 44.904 ;
     RECT  24.653 15.264 24.941 22.488 ;
     RECT  24.796 46.608 25.013 46.632 ;
     RECT  24.617 38.208 25.021 39.576 ;
     RECT  24.725 3.168 25.085 5.784 ;
     RECT  24.304 68.976 25.085 69 ;
     RECT  24.803 40.656 25.091 44.904 ;
     RECT  24.689 61.632 25.121 61.8 ;
     RECT  24.653 8.928 25.129 14.136 ;
     RECT  24.545 74.688 25.193 74.712 ;
     RECT  24.941 15.456 25.229 22.488 ;
     RECT  24.304 49.536 25.265 50.664 ;
     RECT  25.265 50.256 25.297 50.664 ;
     RECT  25.229 17.184 25.333 22.488 ;
     RECT  24.304 58.656 25.337 58.68 ;
     RECT  24.46 24.48 25.379 26.28 ;
     RECT  25.091 42.768 25.409 44.904 ;
     RECT  25.333 17.184 25.553 22.776 ;
     RECT  25.091 40.656 25.553 41.64 ;
     RECT  24.515 53.088 25.553 53.928 ;
     RECT  24.46 27.408 25.621 27.432 ;
     RECT  25.021 38.208 25.669 38.472 ;
     RECT  25.129 11.664 25.697 14.136 ;
     RECT  25.021 39.552 25.715 39.576 ;
     RECT  24.725 6.816 25.765 7.368 ;
     RECT  24.304 33.696 25.765 33.72 ;
     RECT  25.765 6.816 25.772 7.656 ;
     RECT  25.129 8.928 25.772 10.44 ;
     RECT  25.621 27.408 25.801 28.248 ;
     RECT  25.553 40.656 25.873 41.448 ;
     RECT  25.379 26.208 26.012 26.28 ;
     RECT  25.801 27.408 26.012 29.064 ;
     RECT  25.621 36.096 26.053 36.12 ;
     RECT  25.697 11.76 26.101 14.136 ;
     RECT  25.229 15.456 26.101 15.864 ;
     RECT  25.297 50.256 26.161 50.856 ;
     RECT  24.515 51.984 26.161 52.008 ;
     RECT  24.796 47.904 26.189 48.504 ;
     RECT  26.053 35.856 26.197 36.936 ;
     RECT  25.553 22.752 26.233 22.776 ;
     RECT  25.379 24.48 26.233 24.648 ;
     RECT  26.012 26.208 26.341 29.064 ;
     RECT  25.409 43.344 26.413 44.904 ;
     RECT  26.189 47.904 26.449 48.984 ;
     RECT  26.161 50.256 26.449 52.008 ;
     RECT  25.553 17.184 26.485 21.768 ;
     RECT  26.341 25.776 26.665 29.064 ;
     RECT  24.689 30.096 26.665 30.12 ;
     RECT  26.449 47.904 26.665 52.008 ;
     RECT  25.085 3.168 26.708 5.304 ;
     RECT  25.772 6.816 26.708 10.44 ;
     RECT  26.101 11.76 26.708 15.864 ;
     RECT  26.485 16.896 26.708 21.768 ;
     RECT  26.233 22.752 26.708 24.648 ;
     RECT  26.665 25.776 26.708 30.12 ;
     RECT  25.765 33.072 26.708 33.72 ;
     RECT  26.197 35.424 26.708 36.936 ;
     RECT  25.669 38.112 26.708 38.472 ;
     RECT  25.873 39.888 26.708 41.448 ;
     RECT  26.413 42.576 26.708 44.904 ;
     RECT  25.441 46.224 26.708 46.248 ;
     RECT  26.665 47.904 26.708 52.2 ;
     RECT  25.553 53.52 26.708 53.928 ;
     RECT  25.121 61.632 26.708 61.656 ;
     RECT  24.304 72.144 26.708 72.168 ;
     RECT  26.708 2.148 26.812 75.612 ;
     RECT  26.812 2.418 27.004 75.342 ;
     RECT  27.004 3.648 27.155 7.656 ;
     RECT  27.004 23.664 27.155 30.264 ;
     RECT  27.004 51.984 27.155 54.024 ;
     RECT  27.155 51.984 27.281 52.44 ;
     RECT  27.004 44.88 27.388 46.152 ;
     RECT  27.155 3.648 27.389 4.152 ;
     RECT  27.155 5.184 27.389 7.656 ;
     RECT  27.155 23.664 27.425 24.984 ;
     RECT  27.004 49.584 27.425 50.904 ;
     RECT  27.155 53.52 27.497 54.024 ;
     RECT  27.004 16.896 27.533 19.848 ;
     RECT  27.004 63.792 27.533 63.816 ;
     RECT  27.004 9.648 27.569 11.976 ;
     RECT  27.004 47.28 27.569 47.88 ;
     RECT  27.004 57.024 27.641 57.336 ;
     RECT  27.497 53.568 27.827 54.024 ;
     RECT  27.641 57.312 27.893 57.336 ;
     RECT  27.569 9.648 27.929 11.832 ;
     RECT  27.004 58.608 27.929 58.728 ;
     RECT  27.004 13.008 27.971 15.864 ;
     RECT  27.533 17.616 27.997 19.848 ;
     RECT  27.004 21.072 27.997 21.528 ;
     RECT  27.569 47.856 28.001 47.88 ;
     RECT  27.971 13.008 28.021 15.24 ;
     RECT  27.004 22.608 28.021 22.632 ;
     RECT  27.929 58.608 28.037 58.632 ;
     RECT  27.929 11.664 28.067 11.832 ;
     RECT  27.155 26.256 28.069 30.264 ;
     RECT  27.004 35.424 28.105 35.448 ;
     RECT  27.929 9.648 28.108 10.584 ;
     RECT  28.021 22.56 28.108 22.632 ;
     RECT  27.389 3.648 28.141 3.864 ;
     RECT  27.997 17.616 28.141 21.528 ;
     RECT  27.004 38.208 28.141 38.472 ;
     RECT  28.141 3.552 28.145 3.864 ;
     RECT  28.021 12.96 28.145 15.24 ;
     RECT  27.004 33.072 28.213 33.096 ;
     RECT  28.141 67.248 28.213 67.272 ;
     RECT  27.389 5.184 28.253 7.368 ;
     RECT  28.141 17.616 28.297 22.248 ;
     RECT  28.213 32.88 28.297 33.672 ;
     RECT  28.145 3.552 28.397 3.576 ;
     RECT  28.145 13.008 28.397 15.24 ;
     RECT  27.388 44.88 28.433 45.576 ;
     RECT  28.108 9.648 28.453 9.96 ;
     RECT  28.105 34.752 28.465 35.448 ;
     RECT  28.177 41.904 28.465 41.928 ;
     RECT  28.465 41.904 28.573 42.696 ;
     RECT  28.069 26.256 28.645 30.6 ;
     RECT  28.573 41.616 28.789 42.744 ;
     RECT  27.004 40.464 28.825 40.488 ;
     RECT  28.789 41.616 28.825 43.896 ;
     RECT  27.281 52.416 28.933 52.44 ;
     RECT  27.827 53.568 28.961 53.592 ;
     RECT  28.141 38.208 28.969 38.808 ;
     RECT  28.573 48.432 28.969 48.456 ;
     RECT  27.425 49.584 28.969 50.376 ;
     RECT  28.933 52.224 28.997 52.44 ;
     RECT  28.961 53.568 28.997 54.12 ;
     RECT  28.253 5.184 29.041 5.304 ;
     RECT  28.933 17.088 29.077 17.112 ;
     RECT  28.645 26.208 29.077 30.6 ;
     RECT  29.077 16.896 29.113 17.112 ;
     RECT  29.113 16.656 29.149 17.112 ;
     RECT  28.969 48.432 29.149 50.856 ;
     RECT  28.067 11.712 29.185 11.832 ;
     RECT  28.453 9.072 29.221 9.96 ;
     RECT  29.185 11.184 29.221 11.832 ;
     RECT  28.397 13.008 29.221 14.712 ;
     RECT  28.213 66.816 29.221 67.272 ;
     RECT  27.004 73.92 29.257 74.616 ;
     RECT  28.465 34.752 29.269 35.496 ;
     RECT  28.357 37.056 29.269 37.08 ;
     RECT  29.077 63.264 29.269 63.288 ;
     RECT  29.221 66.384 29.269 67.272 ;
     RECT  28.825 40.464 29.365 43.896 ;
     RECT  28.297 18.432 29.401 22.248 ;
     RECT  28.165 23.376 29.401 23.4 ;
     RECT  28.609 3.408 29.408 3.432 ;
     RECT  29.041 5.04 29.408 5.304 ;
     RECT  28.253 6.816 29.408 7.368 ;
     RECT  29.221 9.072 29.408 14.712 ;
     RECT  29.149 15.792 29.408 17.112 ;
     RECT  29.401 18.432 29.408 23.4 ;
     RECT  27.425 24.48 29.408 24.984 ;
     RECT  29.077 26.208 29.408 31.512 ;
     RECT  28.297 32.88 29.408 33.624 ;
     RECT  29.269 34.752 29.408 37.08 ;
     RECT  28.969 38.208 29.408 39.336 ;
     RECT  29.365 40.32 29.408 43.896 ;
     RECT  28.433 44.88 29.408 45.528 ;
     RECT  29.149 47.856 29.408 50.856 ;
     RECT  28.997 52.224 29.408 54.12 ;
     RECT  28.897 55.152 29.408 55.176 ;
     RECT  29.269 57.6 29.408 57.624 ;
     RECT  27.004 61.632 29.408 61.656 ;
     RECT  29.269 63.024 29.408 63.288 ;
     RECT  29.269 66.384 29.408 67.848 ;
     RECT  27.004 72.144 29.408 72.168 ;
     RECT  29.257 73.92 29.408 74.712 ;
     RECT  29.408 2.148 29.512 75.612 ;
     RECT  29.512 2.418 29.704 75.342 ;
     RECT  29.704 14.688 29.729 33.672 ;
     RECT  29.704 40.32 29.729 41.4 ;
     RECT  29.704 47.856 29.837 47.88 ;
     RECT  29.729 14.784 29.843 33.672 ;
     RECT  29.704 60.144 29.843 61.656 ;
     RECT  29.704 62.736 29.843 63.864 ;
     RECT  29.843 14.784 29.909 20.52 ;
     RECT  29.843 21.648 29.909 27.384 ;
     RECT  29.843 28.752 29.909 33.672 ;
     RECT  29.704 49.584 29.981 51.912 ;
     RECT  29.843 61.632 30.035 61.656 ;
     RECT  29.704 69.12 30.035 69.144 ;
     RECT  29.704 72.144 30.035 72.168 ;
     RECT  29.909 21.648 30.125 26.424 ;
     RECT  30.125 21.648 30.169 26.376 ;
     RECT  29.797 0.096 30.193 0.12 ;
     RECT  29.909 14.784 30.227 17.352 ;
     RECT  29.909 18.672 30.227 20.52 ;
     RECT  30.169 21.648 30.227 24.888 ;
     RECT  29.704 36.096 30.233 37.08 ;
     RECT  29.981 50.256 30.275 51.912 ;
     RECT  30.193 0.096 30.301 0.552 ;
     RECT  29.704 13.056 30.305 13.608 ;
     RECT  30.227 21.648 30.305 23.736 ;
     RECT  29.909 29.76 30.305 33.672 ;
     RECT  29.704 43.536 30.341 43.56 ;
     RECT  30.301 0.096 30.467 1.128 ;
     RECT  30.227 14.784 30.521 16.92 ;
     RECT  30.233 36.096 30.521 36.504 ;
     RECT  29.704 3.408 30.529 3.432 ;
     RECT  30.305 29.76 30.593 32.328 ;
     RECT  30.467 0.096 30.659 0.552 ;
     RECT  30.305 21.648 30.665 23.544 ;
     RECT  29.704 44.88 30.697 45.528 ;
     RECT  29.729 40.416 30.707 41.4 ;
     RECT  30.305 13.296 30.733 13.608 ;
     RECT  29.704 46.752 30.733 46.776 ;
     RECT  29.704 6.816 30.737 6.84 ;
     RECT  29.704 34.896 30.769 34.92 ;
     RECT  30.521 36.096 30.769 36.408 ;
     RECT  29.843 60.144 30.769 60.168 ;
     RECT  30.689 1.728 30.773 1.752 ;
     RECT  29.704 4.8 30.805 5.736 ;
     RECT  30.769 60.048 30.805 60.168 ;
     RECT  30.521 14.784 30.809 16.584 ;
     RECT  30.227 18.768 30.809 20.52 ;
     RECT  29.704 56.736 30.812 56.904 ;
     RECT  30.809 18.768 30.845 20.136 ;
     RECT  30.227 24.864 30.845 24.888 ;
     RECT  30.275 50.256 30.881 51.528 ;
     RECT  30.812 56.736 30.899 57.72 ;
     RECT  30.305 33.552 30.908 33.672 ;
     RECT  30.769 34.896 30.908 36.408 ;
     RECT  30.659 0.48 30.947 0.552 ;
     RECT  30.805 3.984 30.953 5.736 ;
     RECT  29.843 62.736 30.985 63 ;
     RECT  30.805 60.048 30.988 60.696 ;
     RECT  29.704 11.184 31.021 11.208 ;
     RECT  30.697 44.592 31.021 45.528 ;
     RECT  30.947 0.48 31.043 0.504 ;
     RECT  29.909 28.752 31.093 28.776 ;
     RECT  29.704 38.208 31.093 38.232 ;
     RECT  30.913 39.312 31.093 39.336 ;
     RECT  30.985 62.592 31.093 63 ;
     RECT  30.845 18.768 31.097 20.04 ;
     RECT  31.093 61.728 31.133 63 ;
     RECT  31.133 61.728 31.165 61.752 ;
     RECT  31.021 10.992 31.201 11.208 ;
     RECT  30.665 21.648 31.201 21.672 ;
     RECT  30.881 50.256 31.309 50.856 ;
     RECT  31.133 62.976 31.333 63 ;
     RECT  31.093 28.512 31.345 28.776 ;
     RECT  30.841 42.768 31.345 42.792 ;
     RECT  30.908 1.776 31.381 2.28 ;
     RECT  31.093 37.632 31.453 38.232 ;
     RECT  31.093 39.312 31.453 39.864 ;
     RECT  31.021 44.448 31.477 45.768 ;
     RECT  30.733 46.752 31.489 46.968 ;
     RECT  30.169 26.256 31.525 26.376 ;
     RECT  31.381 1.776 31.561 2.328 ;
     RECT  31.333 62.976 31.628 63.144 ;
     RECT  31.345 28.368 31.669 28.776 ;
     RECT  30.665 22.704 31.705 23.544 ;
     RECT  31.477 43.872 31.705 45.768 ;
     RECT  31.489 46.752 31.705 47.064 ;
     RECT  31.669 27.408 31.741 28.776 ;
     RECT  30.593 29.904 31.741 32.328 ;
     RECT  31.561 68.688 31.777 68.712 ;
     RECT  30.809 15.456 31.813 16.584 ;
     RECT  31.561 1.776 31.841 2.904 ;
     RECT  31.813 15.456 31.861 17.064 ;
     RECT  31.345 42.768 31.885 42.84 ;
     RECT  31.705 43.872 31.885 47.064 ;
     RECT  30.899 56.736 31.885 57 ;
     RECT  31.201 21.504 31.909 21.672 ;
     RECT  31.705 22.704 31.909 23.928 ;
     RECT  31.525 25.776 31.909 26.376 ;
     RECT  30.988 60.048 31.916 60.072 ;
     RECT  31.201 10.992 31.921 11.688 ;
     RECT  31.885 42.768 31.921 47.064 ;
     RECT  29.704 9.072 31.957 9.096 ;
     RECT  31.921 10.752 31.957 11.688 ;
     RECT  30.733 13.296 31.957 13.656 ;
     RECT  31.309 49.92 31.957 50.856 ;
     RECT  31.916 52.992 31.957 53.016 ;
     RECT  31.916 59.712 31.957 60.072 ;
     RECT  31.777 68.208 31.993 68.712 ;
     RECT  31.097 18.96 32.065 20.04 ;
     RECT  31.909 25.152 32.065 26.376 ;
     RECT  31.741 27.408 32.065 32.328 ;
     RECT  31.957 0.576 32.099 0.696 ;
     RECT  31.841 1.728 32.108 2.904 ;
     RECT  30.953 4.56 32.108 5.736 ;
     RECT  31.237 7.344 32.108 7.368 ;
     RECT  31.957 8.784 32.108 9.096 ;
     RECT  31.957 10.656 32.108 11.688 ;
     RECT  31.957 13.296 32.108 13.704 ;
     RECT  31.861 15.456 32.108 17.112 ;
     RECT  32.065 18.816 32.108 20.04 ;
     RECT  31.909 21.504 32.108 23.928 ;
     RECT  32.065 25.152 32.108 32.328 ;
     RECT  30.908 33.552 32.108 36.408 ;
     RECT  31.453 37.632 32.108 39.864 ;
     RECT  30.707 41.04 32.108 41.4 ;
     RECT  31.921 42.768 32.108 47.352 ;
     RECT  31.957 48.96 32.108 50.856 ;
     RECT  31.957 52.992 32.108 53.208 ;
     RECT  31.885 56.736 32.108 57.144 ;
     RECT  31.957 58.944 32.108 60.072 ;
     RECT  31.165 61.68 32.108 61.752 ;
     RECT  31.628 62.976 32.108 63.192 ;
     RECT  31.453 66.672 32.108 66.696 ;
     RECT  31.993 67.824 32.108 68.712 ;
     RECT  31.669 70.704 32.108 70.728 ;
     RECT  32.099 0.576 32.149 0.648 ;
     RECT  32.108 1.728 32.212 75.612 ;
     RECT  32.212 1.728 32.404 75.342 ;
     RECT  32.404 21.504 32.465 21.672 ;
     RECT  32.404 22.8 32.465 24.216 ;
     RECT  32.404 18.72 32.501 19.56 ;
     RECT  32.404 59.184 32.501 63 ;
     RECT  32.404 25.2 32.537 30.456 ;
     RECT  32.404 33.504 32.579 41.736 ;
     RECT  32.579 35.28 32.681 41.736 ;
     RECT  32.149 0.096 32.717 0.648 ;
     RECT  32.681 35.28 32.753 39.912 ;
     RECT  32.501 62.448 32.753 63 ;
     RECT  32.404 3.408 32.761 5.16 ;
     RECT  32.753 62.544 32.789 63 ;
     RECT  32.717 0.096 32.933 0.6 ;
     RECT  32.404 14.832 33.141 17.112 ;
     RECT  33.141 14.832 33.148 17.016 ;
     RECT  32.501 18.72 33.185 19.368 ;
     RECT  32.753 39.744 33.221 39.912 ;
     RECT  32.404 71.424 33.221 71.448 ;
     RECT  32.404 45.6 33.257 50.856 ;
     RECT  33.185 18.816 33.293 19.368 ;
     RECT  32.404 72.48 33.293 72.504 ;
     RECT  33.257 45.6 33.299 49.608 ;
     RECT  32.501 59.184 33.329 60.888 ;
     RECT  32.404 1.728 33.397 2.28 ;
     RECT  32.404 10.992 33.397 11.688 ;
     RECT  32.404 42.816 33.397 44.28 ;
     RECT  33.299 45.6 33.397 49.56 ;
     RECT  32.404 57.696 33.397 58.008 ;
     RECT  32.404 68.448 33.433 68.472 ;
     RECT  32.761 3.408 33.443 4.584 ;
     RECT  33.397 42.816 33.443 49.56 ;
     RECT  32.404 32.256 33.469 32.472 ;
     RECT  33.397 1.728 33.493 2.328 ;
     RECT  32.465 22.8 33.505 24.024 ;
     RECT  32.537 25.2 33.505 25.656 ;
     RECT  33.433 68.448 33.505 69 ;
     RECT  32.753 35.28 33.541 38.232 ;
     RECT  32.404 65.04 33.545 65.304 ;
     RECT  33.443 3.984 33.589 4.584 ;
     RECT  32.681 41.088 33.613 41.736 ;
     RECT  33.443 42.816 33.613 47.688 ;
     RECT  33.505 67.872 33.617 69 ;
     RECT  32.537 26.64 33.637 30.456 ;
     RECT  33.469 31.536 33.637 32.472 ;
     RECT  33.469 20.4 33.649 20.424 ;
     RECT  32.579 33.888 33.653 34.2 ;
     RECT  33.617 67.872 33.689 67.896 ;
     RECT  33.613 41.088 33.725 47.688 ;
     RECT  33.725 41.088 33.731 44.424 ;
     RECT  33.397 10.272 33.761 11.688 ;
     RECT  33.148 15.504 33.761 17.016 ;
     RECT  33.293 18.96 33.761 19.368 ;
     RECT  33.617 68.976 33.761 69 ;
     RECT  32.404 6.384 33.781 8.808 ;
     RECT  33.649 20.4 33.793 20.52 ;
     RECT  32.465 21.648 33.793 21.672 ;
     RECT  33.329 59.952 33.793 60.888 ;
     RECT  33.761 10.608 33.829 11.688 ;
     RECT  33.649 53.568 33.932 53.592 ;
     RECT  33.781 5.76 33.973 8.808 ;
     RECT  32.789 62.976 33.973 63 ;
     RECT  33.493 1.728 33.977 2.952 ;
     RECT  33.932 53.52 34.009 53.592 ;
     RECT  33.397 56.928 34.045 58.008 ;
     RECT  33.793 59.952 34.045 60.984 ;
     RECT  33.973 62.16 34.045 63 ;
     RECT  33.505 22.8 34.081 25.656 ;
     RECT  33.637 26.64 34.081 32.52 ;
     RECT  34.045 56.928 34.081 58.68 ;
     RECT  34.045 59.952 34.153 63 ;
     RECT  33.973 64.416 34.153 64.44 ;
     RECT  32.933 0.096 34.189 0.216 ;
     RECT  34.189 0.048 34.225 0.216 ;
     RECT  33.653 34.08 34.225 34.2 ;
     RECT  33.541 35.184 34.225 38.232 ;
     RECT  33.829 10.608 34.261 12.024 ;
     RECT  32.404 13.152 34.261 13.848 ;
     RECT  33.761 18.96 34.261 19.032 ;
     RECT  33.443 48.672 34.261 49.56 ;
     RECT  33.257 50.832 34.261 50.856 ;
     RECT  33.577 70.512 34.261 70.632 ;
     RECT  34.261 48.672 34.367 50.856 ;
     RECT  33.221 39.744 34.369 39.768 ;
     RECT  33.731 41.088 34.369 44.28 ;
     RECT  34.009 52.704 34.405 53.592 ;
     RECT  34.364 54.72 34.405 54.744 ;
     RECT  33.973 5.136 34.441 8.808 ;
     RECT  33.977 1.776 34.501 2.952 ;
     RECT  33.589 3.984 34.501 4.056 ;
     RECT  33.793 20.4 34.513 21.672 ;
     RECT  34.367 48.672 34.549 51.144 ;
     RECT  34.405 52.704 34.549 55.464 ;
     RECT  34.501 1.776 34.585 4.056 ;
     RECT  34.441 5.136 34.585 8.856 ;
     RECT  34.585 1.776 34.645 8.856 ;
     RECT  34.261 10.608 34.652 13.848 ;
     RECT  34.225 34.08 34.693 38.232 ;
     RECT  33.725 45.504 34.693 47.688 ;
     RECT  34.549 48.672 34.693 55.464 ;
     RECT  33.761 16.224 34.729 17.016 ;
     RECT  34.261 18.144 34.729 19.032 ;
     RECT  34.261 70.512 34.765 70.68 ;
     RECT  34.645 1.776 34.808 8.904 ;
     RECT  34.652 10.608 34.808 14.328 ;
     RECT  34.729 16.224 34.808 19.032 ;
     RECT  34.513 20.112 34.808 21.672 ;
     RECT  34.081 22.8 34.808 32.52 ;
     RECT  34.693 33.552 34.808 38.232 ;
     RECT  34.369 39.744 34.808 44.28 ;
     RECT  34.693 45.504 34.808 55.464 ;
     RECT  34.081 56.544 34.808 58.68 ;
     RECT  34.153 59.952 34.808 64.44 ;
     RECT  34.357 65.424 34.808 65.448 ;
     RECT  34.765 69.792 34.808 70.68 ;
     RECT  34.808 1.776 34.912 75.612 ;
     RECT  34.912 1.776 35.029 75.342 ;
     RECT  35.029 1.728 35.104 75.342 ;
     RECT  35.104 18.144 35.129 18.744 ;
     RECT  35.104 61.344 35.201 63.96 ;
     RECT  34.225 0.048 35.221 0.552 ;
     RECT  35.104 1.728 35.221 5.208 ;
     RECT  35.104 32.928 35.26 38.232 ;
     RECT  35.104 44.976 35.267 54.408 ;
     RECT  35.104 55.44 35.267 58.152 ;
     RECT  35.104 39.744 35.273 43.32 ;
     RECT  35.104 24.912 35.309 30.456 ;
     RECT  35.267 44.976 35.315 49.032 ;
     RECT  35.267 50.016 35.315 54.408 ;
     RECT  35.201 61.872 35.315 63.96 ;
     RECT  35.104 59.232 35.356 60.072 ;
     RECT  35.104 6.24 35.363 13.08 ;
     RECT  35.273 41.376 35.381 43.32 ;
     RECT  35.363 8.448 35.417 13.08 ;
     RECT  35.104 69.792 35.417 70.296 ;
     RECT  35.315 51.12 35.453 54.408 ;
     RECT  35.104 64.944 35.561 65.448 ;
     RECT  35.104 16.08 35.597 17.064 ;
     RECT  35.104 67.248 35.597 68.232 ;
     RECT  35.417 69.792 35.597 69.816 ;
     RECT  35.597 16.368 35.633 17.064 ;
     RECT  35.104 20.064 35.633 20.568 ;
     RECT  35.453 51.12 35.633 54.36 ;
     RECT  35.267 55.44 35.633 55.464 ;
     RECT  35.417 8.448 35.699 11.448 ;
     RECT  35.104 14.304 35.699 15.048 ;
     RECT  35.633 17.04 35.699 17.064 ;
     RECT  35.633 20.112 35.705 20.568 ;
     RECT  35.699 9.936 35.74 10.632 ;
     RECT  35.417 12.528 35.74 13.08 ;
     RECT  35.633 51.264 35.74 54.36 ;
     RECT  35.561 64.944 35.785 65.16 ;
     RECT  35.315 44.976 35.813 46.872 ;
     RECT  35.309 25.488 35.849 30.456 ;
     RECT  35.315 48.432 35.885 49.032 ;
     RECT  35.315 50.016 35.885 50.136 ;
     RECT  35.885 50.112 35.891 50.136 ;
     RECT  35.315 61.872 35.891 63.912 ;
     RECT  35.267 57.216 35.939 58.152 ;
     RECT  35.885 48.432 35.957 48.504 ;
     RECT  35.939 58.128 35.957 58.152 ;
     RECT  35.381 41.568 35.98 43.32 ;
     RECT  35.356 60.048 35.987 60.072 ;
     RECT  35.891 61.872 35.987 62.952 ;
     RECT  35.597 67.248 35.987 68.184 ;
     RECT  35.74 51.264 35.993 54.072 ;
     RECT  35.987 62.928 36.028 62.952 ;
     RECT  35.987 67.248 36.028 67.272 ;
     RECT  35.705 20.4 36.029 20.568 ;
     RECT  35.104 22.8 36.029 23.832 ;
     RECT  35.987 61.872 36.029 61.896 ;
     RECT  35.129 18.48 36.065 18.744 ;
     RECT  35.699 14.304 36.101 14.328 ;
     RECT  35.813 45.696 36.101 46.872 ;
     RECT  35.993 52.08 36.109 54.072 ;
     RECT  36.109 53.856 36.124 54.072 ;
     RECT  35.98 42.288 36.133 43.32 ;
     RECT  35.363 6.24 36.227 7.416 ;
     RECT  36.109 52.08 36.245 52.536 ;
     RECT  35.221 0.048 36.277 5.208 ;
     RECT  36.227 6.24 36.277 6.264 ;
     RECT  36.227 7.392 36.325 7.416 ;
     RECT  36.277 0.048 36.353 6.264 ;
     RECT  36.029 20.544 36.353 20.568 ;
     RECT  35.785 65.136 36.353 65.16 ;
     RECT  36.133 42.288 36.371 43.944 ;
     RECT  35.849 29.184 36.385 30.456 ;
     RECT  35.104 31.776 36.385 31.944 ;
     RECT  35.957 48.432 36.385 48.456 ;
     RECT  36.101 45.696 36.389 45.72 ;
     RECT  36.371 42.288 36.412 43.32 ;
     RECT  36.353 0.096 36.425 6.264 ;
     RECT  36.101 46.704 36.493 46.872 ;
     RECT  36.385 47.856 36.493 48.456 ;
     RECT  36.425 0.096 36.533 4.68 ;
     RECT  35.26 33.648 36.533 38.232 ;
     RECT  36.245 52.416 36.533 52.536 ;
     RECT  36.385 29.184 36.565 31.944 ;
     RECT  36.029 23.28 36.637 23.832 ;
     RECT  36.533 0.144 36.641 4.68 ;
     RECT  36.641 0.144 36.659 1.176 ;
     RECT  36.659 0.144 36.785 0.312 ;
     RECT  35.74 10.608 36.997 10.632 ;
     RECT  36.565 21.552 36.997 21.576 ;
     RECT  36.637 23.28 36.997 24.504 ;
     RECT  35.849 25.488 36.997 27.624 ;
     RECT  35.699 8.448 37.045 8.856 ;
     RECT  36.997 10.608 37.045 10.92 ;
     RECT  36.997 23.28 37.1 27.624 ;
     RECT  36.325 7.392 37.244 7.464 ;
     RECT  37.045 8.448 37.244 10.92 ;
     RECT  36.425 5.664 37.249 6.264 ;
     RECT  37.244 7.392 37.249 10.92 ;
     RECT  36.641 2.148 37.508 4.68 ;
     RECT  37.249 5.664 37.508 10.92 ;
     RECT  35.74 12.528 37.508 12.552 ;
     RECT  36.997 21.552 37.508 22.2 ;
     RECT  37.1 23.28 37.508 27.912 ;
     RECT  36.565 29.184 37.508 32.184 ;
     RECT  36.533 33.648 37.508 34.2 ;
     RECT  36.533 35.376 37.508 38.232 ;
     RECT  35.273 39.744 37.508 39.768 ;
     RECT  36.412 42.288 37.508 43.272 ;
     RECT  36.493 46.704 37.508 48.456 ;
     RECT  36.533 52.416 37.508 52.44 ;
     RECT  36.124 54.048 37.508 54.072 ;
     RECT  37.508 2.148 37.612 75.612 ;
     RECT  36.785 0.24 37.685 0.312 ;
     RECT  37.612 2.256 37.804 75.342 ;
     RECT  37.804 35.76 37.937 35.784 ;
     RECT  37.804 2.256 37.955 3.048 ;
     RECT  37.804 4.56 37.981 4.68 ;
     RECT  37.804 6.864 37.981 6.888 ;
     RECT  37.804 33.6 38.009 33.624 ;
     RECT  37.955 2.88 38.051 2.904 ;
     RECT  37.981 4.656 38.051 4.68 ;
     RECT  37.804 39.744 38.729 39.768 ;
     RECT  37.685 0.24 39.125 0.264 ;
     RECT  37.804 38.208 40.208 38.232 ;
     RECT  40.208 2.148 40.312 75.612 ;
     RECT  40.312 2.418 40.504 75.342 ;
     RECT  40.504 39.36 41.027 39.912 ;
     RECT  40.504 38.208 43.081 38.232 ;
     RECT  43.081 38.208 43.121 38.376 ;
     RECT  43.121 38.352 43.164 38.376 ;
     RECT  41.027 39.36 43.164 39.384 ;
    LAYER M5 ;
     RECT  30.432 0.016 36.696 1.139 ;
     RECT  30.72 1.139 36.696 1.763 ;
     RECT  6.432 0.016 12.696 2.003 ;
     RECT  21.552 0.016 21.576 2.137 ;
     RECT  30.816 1.763 36.696 2.137 ;
     RECT  2.4 2.137 2.52 2.151 ;
     RECT  5.1 2.137 5.22 2.151 ;
     RECT  13.2 2.137 13.32 2.151 ;
     RECT  15.9 2.137 16.02 2.151 ;
     RECT  18.6 2.137 18.72 2.151 ;
     RECT  21.3 2.137 21.576 2.151 ;
     RECT  24 2.137 24.12 2.151 ;
     RECT  26.7 2.137 26.82 2.151 ;
     RECT  29.4 2.137 29.52 2.151 ;
     RECT  30.816 2.137 37.62 2.151 ;
     RECT  40.2 2.137 40.32 2.151 ;
     RECT  5.1 2.151 5.412 2.197 ;
     RECT  6.432 2.003 12.168 2.197 ;
     RECT  30.816 2.151 37.812 2.245 ;
     RECT  5.1 2.197 12.168 2.773 ;
     RECT  18.6 2.151 18.912 2.821 ;
     RECT  30.816 2.245 37.944 2.869 ;
     RECT  15.9 2.151 16.212 3.061 ;
     RECT  29.4 2.151 29.712 3.397 ;
     RECT  30.816 2.869 38.04 3.397 ;
     RECT  4.944 2.773 12.168 3.443 ;
     RECT  12.144 3.443 12.168 3.877 ;
     RECT  13.2 2.151 13.512 3.877 ;
     RECT  21.3 2.151 21.612 3.925 ;
     RECT  12.144 3.877 13.512 4.069 ;
     RECT  15.216 3.061 16.212 4.069 ;
     RECT  26.7 2.151 27.012 4.117 ;
     RECT  18.6 2.821 19.032 4.355 ;
     RECT  12.144 4.069 16.212 4.547 ;
     RECT  29.4 3.397 38.04 4.643 ;
     RECT  4.944 3.443 11.16 4.691 ;
     RECT  32.1 4.643 38.04 4.691 ;
     RECT  4.944 4.691 8.76 4.787 ;
     RECT  21.12 3.925 21.612 5.077 ;
     RECT  9.744 4.691 11.16 5.171 ;
     RECT  26.7 4.117 27.144 5.269 ;
     RECT  26.7 5.269 27.336 5.605 ;
     RECT  4.992 4.787 8.76 5.653 ;
     RECT  9.744 5.171 10.812 5.653 ;
     RECT  24 2.151 24.312 5.653 ;
     RECT  12.144 4.547 13.512 5.699 ;
     RECT  29.4 4.643 30.984 5.747 ;
     RECT  32.1 4.691 37.944 5.843 ;
     RECT  12.288 5.699 13.512 5.893 ;
     RECT  26.7 5.605 28.152 6.275 ;
     RECT  21.12 5.077 22.248 6.323 ;
     RECT  21.12 6.323 22.2 6.613 ;
     RECT  20.208 6.613 22.2 6.803 ;
     RECT  37.5 5.843 37.944 6.899 ;
     RECT  32.1 5.843 36.36 7.187 ;
     RECT  26.7 6.275 27.336 7.331 ;
     RECT  29.4 5.747 29.712 7.333 ;
     RECT  23.904 5.653 24.312 7.379 ;
     RECT  32.1 7.187 35.352 7.379 ;
     RECT  15.216 4.547 16.212 7.381 ;
     RECT  18.6 4.355 18.912 7.381 ;
     RECT  26.7 7.331 27.192 7.381 ;
     RECT  36.336 7.187 36.36 7.475 ;
     RECT  4.992 5.653 10.812 7.621 ;
     RECT  37.5 6.899 37.812 7.765 ;
     RECT  21.12 6.803 22.2 7.861 ;
     RECT  32.1 7.379 33.432 8.003 ;
     RECT  32.1 8.003 33.24 8.051 ;
     RECT  18.48 7.381 18.912 8.195 ;
     RECT  37.296 7.765 37.812 8.485 ;
     RECT  12.288 5.893 13.608 8.533 ;
     RECT  34.416 7.379 35.352 8.579 ;
     RECT  34.56 8.579 35.352 8.627 ;
     RECT  15.216 7.381 16.488 8.723 ;
     RECT  11.808 8.533 13.608 8.771 ;
     RECT  20.544 7.861 22.2 8.821 ;
     RECT  24 7.379 24.312 8.821 ;
     RECT  19.92 8.821 22.2 8.867 ;
     RECT  34.656 8.627 35.352 8.915 ;
     RECT  4.608 7.621 10.812 9.013 ;
     RECT  11.808 8.771 13.512 9.013 ;
     RECT  28.464 7.333 29.712 9.107 ;
     RECT  4.608 9.013 13.512 9.395 ;
     RECT  25.824 7.381 27.192 9.395 ;
     RECT  34.704 8.915 35.352 9.397 ;
     RECT  21.12 8.867 22.2 9.445 ;
     RECT  4.608 9.395 10.92 9.539 ;
     RECT  21.12 9.445 22.824 9.587 ;
     RECT  26.112 9.395 27.192 9.637 ;
     RECT  4.608 9.539 8.76 9.779 ;
     RECT  29.184 9.107 29.712 9.779 ;
     RECT  24 8.821 24.408 10.165 ;
     RECT  26.112 9.637 28.056 10.307 ;
     RECT  33.552 10.501 33.576 10.597 ;
     RECT  34.704 9.397 35.688 10.597 ;
     RECT  18.6 8.195 18.912 10.837 ;
     RECT  21.3 9.587 22.2 10.837 ;
     RECT  19.92 8.867 19.944 10.883 ;
     RECT  7.68 9.779 8.76 10.931 ;
     RECT  9.744 9.539 10.92 10.931 ;
     RECT  37.056 8.485 37.812 10.931 ;
     RECT  12.288 9.395 13.512 11.221 ;
     RECT  9.792 10.931 10.92 11.317 ;
     RECT  21.3 10.837 22.776 11.411 ;
     RECT  33.552 10.597 35.688 11.459 ;
     RECT  21.3 11.411 22.008 11.509 ;
     RECT  24 10.165 25.08 11.653 ;
     RECT  18 10.837 18.912 11.747 ;
     RECT  33.552 11.459 35.208 12.035 ;
     RECT  24 11.653 25.128 12.037 ;
     RECT  9.792 11.317 11.016 12.373 ;
     RECT  12 11.221 13.512 12.373 ;
     RECT  26.7 10.307 28.056 12.517 ;
     RECT  34.704 12.035 35.208 12.517 ;
     RECT  23.52 12.037 25.128 12.755 ;
     RECT  26.208 12.517 28.056 12.995 ;
     RECT  29.232 9.779 29.712 12.997 ;
     RECT  15.216 8.723 16.212 13.043 ;
     RECT  26.208 12.995 27.192 13.333 ;
     RECT  20.496 11.509 22.008 13.475 ;
     RECT  29.184 12.997 29.712 13.573 ;
     RECT  32.1 8.051 32.412 13.573 ;
     RECT  33.552 12.035 33.576 13.573 ;
     RECT  7.8 10.931 8.76 14.197 ;
     RECT  9.792 12.373 13.512 14.197 ;
     RECT  21.3 13.475 22.008 14.197 ;
     RECT  15.312 13.043 16.212 14.291 ;
     RECT  15.36 14.291 16.212 14.773 ;
     RECT  29.184 13.573 30.072 14.819 ;
     RECT  26.112 13.333 27.192 14.867 ;
     RECT  26.208 14.867 27.192 14.915 ;
     RECT  23.52 12.755 24.312 14.917 ;
     RECT  7.8 14.197 13.512 15.011 ;
     RECT  32.1 13.573 33.576 15.059 ;
     RECT  21.3 14.197 22.2 15.155 ;
     RECT  15.36 14.773 16.584 15.203 ;
     RECT  23.52 14.917 24.456 15.253 ;
     RECT  20.16 14.197 20.184 15.347 ;
     RECT  23.52 15.253 24.504 15.349 ;
     RECT  4.608 9.779 6.264 15.397 ;
     RECT  4.416 15.397 6.264 15.731 ;
     RECT  26.7 14.915 27.192 15.829 ;
     RECT  23.376 15.349 24.504 16.019 ;
     RECT  33.552 15.059 33.576 16.213 ;
     RECT  34.704 12.517 35.688 16.213 ;
     RECT  4.416 15.731 6.216 16.499 ;
     RECT  32.1 15.059 32.412 16.549 ;
     RECT  4.608 16.499 6.216 16.595 ;
     RECT  15.36 15.203 16.212 16.595 ;
     RECT  33.552 16.213 35.688 16.835 ;
     RECT  29.184 14.819 29.832 16.885 ;
     RECT  21.3 15.155 21.612 16.933 ;
     RECT  20.016 16.501 20.04 16.979 ;
     RECT  31.872 16.549 32.412 16.981 ;
     RECT  33.552 16.835 33.624 16.981 ;
     RECT  34.8 16.835 35.688 17.075 ;
     RECT  31.872 16.981 33.624 17.123 ;
     RECT  23.52 16.019 24.504 17.315 ;
     RECT  23.616 17.315 24.504 17.939 ;
     RECT  26.7 15.829 27.96 17.941 ;
     RECT  29.184 16.885 30.216 17.941 ;
     RECT  7.8 15.011 8.76 18.133 ;
     RECT  4.608 16.595 5.88 18.757 ;
     RECT  6.864 18.133 8.76 18.757 ;
     RECT  26.7 17.941 30.216 18.803 ;
     RECT  24 17.939 24.504 19.045 ;
     RECT  4.608 18.757 8.76 19.139 ;
     RECT  26.7 18.803 29.712 19.139 ;
     RECT  23.184 19.045 24.504 19.235 ;
     RECT  7.8 19.139 8.76 19.333 ;
     RECT  9.792 15.011 13.512 19.333 ;
     RECT  21.12 16.933 21.612 19.333 ;
     RECT  23.184 19.235 24.312 19.333 ;
     RECT  26.7 19.139 28.344 19.333 ;
     RECT  29.4 19.139 29.712 19.909 ;
     RECT  21.12 19.333 24.312 19.955 ;
     RECT  4.608 19.139 6.408 20.533 ;
     RECT  7.8 19.333 13.512 20.533 ;
     RECT  21.3 19.955 24.312 20.579 ;
     RECT  26.208 19.333 28.344 20.579 ;
     RECT  34.8 17.075 35.592 20.579 ;
     RECT  23.376 20.579 24.312 20.725 ;
     RECT  37.5 10.931 37.812 21.541 ;
     RECT  4.608 20.533 13.512 21.637 ;
     RECT  4.416 21.637 13.512 21.685 ;
     RECT  26.208 20.579 28.248 21.685 ;
     RECT  29.4 19.909 29.832 21.685 ;
     RECT  32.1 17.123 32.412 21.829 ;
     RECT  23.376 20.725 25.08 22.021 ;
     RECT  26.208 21.685 29.832 22.021 ;
     RECT  23.376 22.021 29.832 22.067 ;
     RECT  24 22.067 29.832 22.069 ;
     RECT  24 22.069 30.312 22.259 ;
     RECT  4.416 21.685 14.232 22.453 ;
     RECT  24 22.259 28.2 22.499 ;
     RECT  25.344 22.499 28.2 22.595 ;
     RECT  3.984 22.453 14.232 22.741 ;
     RECT  25.344 22.595 27.192 22.787 ;
     RECT  3.984 22.741 14.856 22.835 ;
     RECT  31.92 21.829 32.412 22.883 ;
     RECT  18.6 11.747 18.912 23.125 ;
     RECT  37.008 21.541 37.812 23.363 ;
     RECT  4.608 22.835 14.856 23.555 ;
     RECT  29.4 22.259 30.312 23.555 ;
     RECT  4.608 23.555 14.232 23.603 ;
     RECT  32.1 22.883 32.412 23.893 ;
     RECT  26.7 22.787 27.192 24.131 ;
     RECT  37.5 23.363 37.812 24.469 ;
     RECT  29.4 23.555 30.216 24.563 ;
     RECT  28.176 22.595 28.2 24.899 ;
     RECT  33.552 17.123 33.624 24.901 ;
     RECT  34.8 20.579 35.112 24.901 ;
     RECT  17.664 23.125 18.912 25.139 ;
     RECT  18.6 25.139 18.912 25.525 ;
     RECT  21.3 20.579 22.152 25.621 ;
     RECT  29.4 24.563 30.12 25.715 ;
     RECT  25.344 22.787 25.368 26.243 ;
     RECT  33.552 24.901 35.112 26.243 ;
     RECT  37.008 24.469 37.812 26.243 ;
     RECT  21.168 25.621 22.152 26.245 ;
     RECT  29.4 25.715 29.928 26.245 ;
     RECT  21.168 26.245 22.92 26.291 ;
     RECT  29.28 26.245 29.928 26.291 ;
     RECT  31.92 23.893 32.412 26.339 ;
     RECT  21.3 26.291 22.92 26.437 ;
     RECT  24 22.499 24.312 26.437 ;
     RECT  29.28 26.291 29.832 26.629 ;
     RECT  4.608 23.603 13.704 26.725 ;
     RECT  21.3 26.437 24.312 26.725 ;
     RECT  26.7 24.131 27.144 26.725 ;
     RECT  34.8 26.243 35.112 26.725 ;
     RECT  18.6 25.525 19.08 27.059 ;
     RECT  28.32 26.629 29.832 27.107 ;
     RECT  33.552 26.243 33.624 27.395 ;
     RECT  21.3 26.725 24.408 27.875 ;
     RECT  33.6 27.395 33.624 27.877 ;
     RECT  37.5 26.243 37.812 27.877 ;
     RECT  26.064 26.725 27.144 27.971 ;
     RECT  32.1 26.339 32.412 28.501 ;
     RECT  33.6 27.877 33.672 28.501 ;
     RECT  34.8 26.725 35.832 28.501 ;
     RECT  33.6 28.501 35.832 28.547 ;
     RECT  28.848 27.107 29.832 28.741 ;
     RECT  26.16 27.971 27.144 29.075 ;
     RECT  31.872 28.501 32.412 29.123 ;
     RECT  18.6 27.059 18.912 29.221 ;
     RECT  37.152 27.877 37.812 29.365 ;
     RECT  37.056 29.365 37.812 29.605 ;
     RECT  28.848 28.741 30.552 29.845 ;
     RECT  26.7 29.075 27.144 30.131 ;
     RECT  28.368 29.845 30.552 30.275 ;
     RECT  18.6 29.221 19.272 30.661 ;
     RECT  4.608 26.725 13.944 30.803 ;
     RECT  23.28 27.875 24.408 30.851 ;
     RECT  24 30.851 24.408 31.427 ;
     RECT  28.368 30.275 30.504 31.523 ;
     RECT  18.6 30.661 19.704 31.619 ;
     RECT  21.3 27.875 22.152 31.765 ;
     RECT  15.9 16.595 16.212 31.861 ;
     RECT  36.72 29.605 37.812 31.909 ;
     RECT  33.6 28.547 35.112 31.955 ;
     RECT  36.432 31.909 37.812 32.195 ;
     RECT  21.168 31.765 22.152 32.341 ;
     RECT  32.1 29.123 32.412 32.437 ;
     RECT  33.6 31.955 33.672 32.531 ;
     RECT  15.9 31.861 17.16 32.771 ;
     RECT  28.368 31.523 29.712 32.869 ;
     RECT  34.8 31.955 35.112 32.917 ;
     RECT  4.608 30.803 13.608 33.061 ;
     RECT  14.784 32.485 14.808 33.061 ;
     RECT  4.608 33.061 14.808 33.107 ;
     RECT  4.608 33.107 14.232 33.251 ;
     RECT  28.224 32.869 29.712 33.683 ;
     RECT  30.96 33.589 30.984 34.355 ;
     RECT  32.1 32.437 32.568 34.643 ;
     RECT  34.8 32.917 35.208 34.693 ;
     RECT  36.432 32.195 36.456 34.693 ;
     RECT  34.8 34.693 36.456 34.739 ;
     RECT  4.608 33.251 13.656 34.981 ;
     RECT  33.6 32.531 33.624 35.173 ;
     RECT  33.552 35.173 33.624 35.315 ;
     RECT  18.6 31.619 18.912 35.317 ;
     RECT  34.8 34.739 35.976 35.459 ;
     RECT  17.616 35.317 18.912 35.845 ;
     RECT  26.7 30.131 27.012 35.845 ;
     RECT  28.368 33.683 29.712 36.131 ;
     RECT  15.9 32.771 16.212 36.661 ;
     RECT  28.368 36.131 28.392 37.091 ;
     RECT  15.9 36.661 16.344 37.717 ;
     RECT  17.616 35.845 19.032 37.717 ;
     RECT  26.064 35.845 27.012 38.101 ;
     RECT  15.9 37.717 19.032 38.149 ;
     RECT  15.648 38.149 19.032 38.243 ;
     RECT  25.68 38.101 27.012 38.339 ;
     RECT  24 31.427 24.312 38.437 ;
     RECT  25.68 38.339 25.704 38.437 ;
     RECT  15.648 38.243 17.304 38.725 ;
     RECT  24 38.437 25.704 39.205 ;
     RECT  40.2 2.151 40.512 39.349 ;
     RECT  4.608 34.981 13.704 39.395 ;
     RECT  18.6 38.243 19.032 39.445 ;
     RECT  15.504 38.725 17.304 39.491 ;
     RECT  23.808 39.205 25.704 39.587 ;
     RECT  34.8 35.459 35.112 39.733 ;
     RECT  23.808 39.587 24.792 39.781 ;
     RECT  32.1 34.643 32.412 39.829 ;
     RECT  40.2 39.349 41.016 39.923 ;
     RECT  29.4 36.131 29.712 40.405 ;
     RECT  31.44 39.829 32.412 40.405 ;
     RECT  23.376 39.781 24.792 40.499 ;
     RECT  26.7 38.339 27.012 40.933 ;
     RECT  29.4 40.405 32.52 41.075 ;
     RECT  31.44 41.075 32.52 41.171 ;
     RECT  15.9 39.491 17.304 41.269 ;
     RECT  18.6 39.445 19.176 41.269 ;
     RECT  26.208 40.933 27.012 41.459 ;
     RECT  23.808 40.499 24.792 41.461 ;
     RECT  29.4 41.075 29.712 41.557 ;
     RECT  34.656 39.733 35.112 41.557 ;
     RECT  5.1 39.395 13.704 42.133 ;
     RECT  20.592 32.341 22.152 42.133 ;
     RECT  23.808 41.461 25.08 42.323 ;
     RECT  5.1 42.133 14.136 42.565 ;
     RECT  31.44 41.171 32.412 42.851 ;
     RECT  20.592 42.133 22.392 42.995 ;
     RECT  15.9 41.269 19.176 42.997 ;
     RECT  20.592 42.995 22.152 42.997 ;
     RECT  33.6 35.315 33.624 42.997 ;
     RECT  34.656 41.557 35.928 42.997 ;
     RECT  5.1 42.565 14.76 43.285 ;
     RECT  15.9 42.997 22.152 43.285 ;
     RECT  33.6 42.997 35.928 43.285 ;
     RECT  33.6 43.285 36.36 43.331 ;
     RECT  26.496 41.459 27.012 43.379 ;
     RECT  23.808 42.323 24.312 43.573 ;
     RECT  32.1 42.851 32.412 43.621 ;
     RECT  33.6 43.331 35.112 43.621 ;
     RECT  32.1 43.621 35.112 43.861 ;
     RECT  36.336 43.331 36.36 43.955 ;
     RECT  31.488 43.861 35.112 44.483 ;
     RECT  28.992 41.557 29.712 44.915 ;
     RECT  32.1 44.483 35.112 44.965 ;
     RECT  5.1 43.285 22.152 45.059 ;
     RECT  5.1 45.059 19.32 45.155 ;
     RECT  29.4 44.915 29.712 45.253 ;
     RECT  26.7 43.379 27.012 45.541 ;
     RECT  20.544 45.059 22.152 45.635 ;
     RECT  5.1 45.155 17.304 45.731 ;
     RECT  32.1 44.965 35.304 45.733 ;
     RECT  32.1 45.733 36.072 46.069 ;
     RECT  23.712 43.573 24.312 46.261 ;
     RECT  29.4 45.253 30.504 46.787 ;
     RECT  31.92 46.069 36.072 46.787 ;
     RECT  20.64 45.635 22.152 46.835 ;
     RECT  32.1 46.787 36.072 46.883 ;
     RECT  18.6 45.155 19.32 47.125 ;
     RECT  18.6 47.125 20.28 47.171 ;
     RECT  23.568 46.261 24.312 47.221 ;
     RECT  26.7 45.541 27.336 47.315 ;
     RECT  23.568 47.221 24.744 47.891 ;
     RECT  12.432 45.731 17.304 47.939 ;
     RECT  23.712 47.891 24.744 47.939 ;
     RECT  32.1 46.883 35.304 48.467 ;
     RECT  32.1 48.467 35.208 48.515 ;
     RECT  23.712 47.939 24.312 48.659 ;
     RECT  26.7 47.315 27.012 48.949 ;
     RECT  32.1 48.515 33.288 48.949 ;
     RECT  29.4 46.787 29.712 48.997 ;
     RECT  5.1 45.731 11.448 49.043 ;
     RECT  29.04 48.997 29.712 49.139 ;
     RECT  12.912 47.939 17.304 49.333 ;
     RECT  31.968 48.949 33.288 49.619 ;
     RECT  20.256 47.171 20.28 49.763 ;
     RECT  34.272 48.515 35.208 49.861 ;
     RECT  34.272 49.861 35.256 50.005 ;
     RECT  34.272 50.005 35.832 50.101 ;
     RECT  31.968 49.619 32.412 50.339 ;
     RECT  34.272 50.101 35.88 50.339 ;
     RECT  26.208 48.949 27.012 50.387 ;
     RECT  5.1 49.043 11.4 50.771 ;
     RECT  20.208 49.813 20.232 50.821 ;
     RECT  26.7 50.387 27.012 50.821 ;
     RECT  19.968 50.821 20.232 50.867 ;
     RECT  34.416 50.339 35.88 51.155 ;
     RECT  12.912 49.333 17.352 51.253 ;
     RECT  18.6 47.171 18.912 51.253 ;
     RECT  21.3 46.835 22.152 51.253 ;
     RECT  34.56 51.155 35.88 51.299 ;
     RECT  12.912 51.253 18.912 51.491 ;
     RECT  29.4 49.139 29.712 51.493 ;
     RECT  30.816 51.397 30.84 51.493 ;
     RECT  5.1 50.771 10.92 51.733 ;
     RECT  5.1 51.733 10.968 51.923 ;
     RECT  19.968 50.867 19.992 51.923 ;
     RECT  29.4 51.493 30.84 51.923 ;
     RECT  34.56 51.299 35.832 51.971 ;
     RECT  25.488 50.389 25.512 52.019 ;
     RECT  5.1 51.923 10.92 52.163 ;
     RECT  29.4 51.923 29.712 52.213 ;
     RECT  26.7 50.821 27.144 52.405 ;
     RECT  12.912 51.491 17.352 52.451 ;
     RECT  24 48.659 24.312 52.597 ;
     RECT  32.1 50.339 32.412 52.981 ;
     RECT  29.04 52.213 29.712 53.075 ;
     RECT  34.8 51.971 35.832 53.077 ;
     RECT  21.168 51.253 22.152 53.123 ;
     RECT  31.968 52.981 32.412 53.219 ;
     RECT  34.8 53.077 36.072 53.509 ;
     RECT  24 52.597 24.504 53.603 ;
     RECT  33.984 53.509 36.072 53.891 ;
     RECT  18.6 51.491 18.912 53.893 ;
     RECT  26.7 52.405 27.816 54.035 ;
     RECT  29.4 53.075 29.712 54.085 ;
     RECT  33.984 53.891 35.688 54.371 ;
     RECT  5.1 52.163 10.812 54.565 ;
     RECT  21.3 53.123 22.152 54.661 ;
     RECT  13.2 52.451 17.352 54.755 ;
     RECT  18.6 53.893 19.032 54.755 ;
     RECT  28.992 54.085 29.712 55.187 ;
     RECT  13.2 54.755 17.304 55.381 ;
     RECT  21.12 54.661 22.152 55.523 ;
     RECT  33.984 54.371 35.112 56.341 ;
     RECT  21.12 55.523 21.768 56.531 ;
     RECT  30.816 51.923 30.84 56.869 ;
     RECT  32.1 53.219 32.412 56.869 ;
     RECT  13.056 55.381 17.304 56.965 ;
     RECT  18.6 54.755 18.912 56.965 ;
     RECT  33.984 56.341 35.256 57.205 ;
     RECT  29.28 55.187 29.712 57.635 ;
     RECT  33.984 57.205 35.928 58.163 ;
     RECT  13.056 56.965 18.912 59.171 ;
     RECT  24 53.603 24.312 59.221 ;
     RECT  33.984 58.163 35.112 59.221 ;
     RECT  13.056 59.171 17.304 59.315 ;
     RECT  33.984 59.221 35.304 60.037 ;
     RECT  21.12 56.531 21.72 60.133 ;
     RECT  29.4 57.635 29.712 60.133 ;
     RECT  18.6 59.171 18.912 60.373 ;
     RECT  23.088 59.221 24.312 60.707 ;
     RECT  21.072 60.133 21.768 60.997 ;
     RECT  13.104 59.315 17.304 61.187 ;
     RECT  20.88 60.997 21.768 61.187 ;
     RECT  29.4 60.133 29.832 61.621 ;
     RECT  30.816 56.869 32.412 61.621 ;
     RECT  26.7 54.035 27.384 61.667 ;
     RECT  18.6 60.373 19.512 61.717 ;
     RECT  33.984 60.037 35.976 62.195 ;
     RECT  13.2 61.187 17.304 62.533 ;
     RECT  5.1 54.565 11.784 62.629 ;
     RECT  29.4 61.621 32.412 62.771 ;
     RECT  20.976 61.187 21.768 62.773 ;
     RECT  34.08 62.195 35.976 62.963 ;
     RECT  29.4 62.771 30.024 63.013 ;
     RECT  31.344 62.771 32.412 63.155 ;
     RECT  20.976 62.773 21.864 63.347 ;
     RECT  13.056 62.533 17.304 63.539 ;
     RECT  5.1 62.629 11.928 63.779 ;
     RECT  34.08 62.963 35.88 63.923 ;
     RECT  34.08 63.923 35.304 63.971 ;
     RECT  5.1 63.779 11.64 64.019 ;
     RECT  21.12 63.347 21.864 64.213 ;
     RECT  22.944 64.165 22.968 64.213 ;
     RECT  34.08 63.971 35.112 64.451 ;
     RECT  34.368 64.451 35.112 64.933 ;
     RECT  21.12 64.213 22.968 64.979 ;
     RECT  34.368 64.933 35.736 65.125 ;
     RECT  18.48 61.717 19.512 65.267 ;
     RECT  18.48 65.267 19.176 65.317 ;
     RECT  13.2 63.539 17.304 65.363 ;
     RECT  34.368 65.125 35.976 65.459 ;
     RECT  13.2 65.363 13.608 65.987 ;
     RECT  15.264 65.363 17.304 66.565 ;
     RECT  21.12 64.979 22.008 66.709 ;
     RECT  18.384 65.317 19.176 66.755 ;
     RECT  20.592 66.709 22.008 66.851 ;
     RECT  13.2 65.987 13.512 67.189 ;
     RECT  13.2 67.189 13.656 67.475 ;
     RECT  20.832 66.851 22.008 67.859 ;
     RECT  29.28 63.013 30.024 67.859 ;
     RECT  15.072 66.565 17.304 67.955 ;
     RECT  34.8 65.459 35.976 68.195 ;
     RECT  20.832 67.859 21.864 68.387 ;
     RECT  31.68 63.155 32.412 68.723 ;
     RECT  24 60.707 24.312 68.917 ;
     RECT  6.864 64.019 11.64 69.587 ;
     RECT  15.072 67.955 16.536 69.587 ;
     RECT  7.296 69.587 11.352 69.635 ;
     RECT  23.376 68.917 24.312 69.779 ;
     RECT  18.432 66.755 19.176 69.827 ;
     RECT  34.8 68.195 35.352 69.827 ;
     RECT  9.6 69.635 11.352 70.163 ;
     RECT  13.2 67.475 13.608 70.259 ;
     RECT  18.6 69.827 19.176 70.499 ;
     RECT  21.168 68.387 21.864 70.549 ;
     RECT  20.832 70.549 21.864 70.693 ;
     RECT  7.296 69.635 8.616 71.075 ;
     RECT  20.736 70.693 21.864 71.315 ;
     RECT  7.296 71.075 8.112 71.317 ;
     RECT  13.2 70.259 13.512 71.317 ;
     RECT  10.5 70.163 11.304 71.749 ;
     RECT  15.36 69.587 16.536 71.797 ;
     RECT  24 69.779 24.312 72.085 ;
     RECT  29.4 67.859 30.024 72.179 ;
     RECT  15.36 71.797 16.728 72.467 ;
     RECT  23.088 72.085 24.312 72.467 ;
     RECT  5.1 64.019 5.412 72.901 ;
     RECT  7.104 71.317 8.112 72.901 ;
     RECT  20.736 71.315 21.72 72.947 ;
     RECT  15.36 72.467 16.536 72.995 ;
     RECT  10.5 71.749 11.976 73.093 ;
     RECT  10.176 73.093 11.976 73.235 ;
     RECT  13.2 71.317 13.608 73.283 ;
     RECT  15.36 72.995 16.212 73.477 ;
     RECT  14.688 73.477 16.212 73.571 ;
     RECT  21.072 72.947 21.72 73.763 ;
     RECT  5.1 72.901 8.112 73.909 ;
     RECT  10.176 73.235 11.016 73.909 ;
     RECT  5.1 73.909 9.096 74.053 ;
     RECT  10.08 73.909 11.016 74.053 ;
     RECT  14.688 73.571 14.808 74.339 ;
     RECT  13.2 73.283 13.512 74.581 ;
     RECT  21.3 73.763 21.72 74.723 ;
     RECT  14.784 74.339 14.808 75.155 ;
     RECT  5.1 74.053 11.016 75.253 ;
     RECT  12.384 74.581 13.512 75.253 ;
     RECT  2.4 2.151 2.712 75.609 ;
     RECT  5.1 75.253 13.512 75.609 ;
     RECT  15.9 73.571 16.212 75.609 ;
     RECT  18.6 70.499 18.912 75.609 ;
     RECT  21.3 74.723 21.612 75.609 ;
     RECT  24 72.467 24.312 75.609 ;
     RECT  26.7 61.667 27.012 75.609 ;
     RECT  29.4 72.179 29.712 75.609 ;
     RECT  32.1 68.723 32.412 75.609 ;
     RECT  34.8 69.827 35.112 75.609 ;
     RECT  37.5 32.195 37.812 75.609 ;
     RECT  40.2 39.923 40.512 75.609 ;
     RECT  2.4 75.609 2.52 75.623 ;
     RECT  5.1 75.609 5.22 75.623 ;
     RECT  6.336 75.609 13.32 75.623 ;
     RECT  15.9 75.609 16.02 75.623 ;
     RECT  18.6 75.609 18.72 75.623 ;
     RECT  21.3 75.609 21.576 75.623 ;
     RECT  24 75.609 24.12 75.623 ;
     RECT  26.7 75.609 26.82 75.623 ;
     RECT  29.4 75.609 29.52 75.623 ;
     RECT  32.1 75.609 32.22 75.623 ;
     RECT  34.8 75.609 34.92 75.623 ;
     RECT  37.5 75.609 37.62 75.623 ;
     RECT  40.2 75.609 40.32 75.623 ;
     RECT  6.336 75.623 12.696 77.603 ;
     RECT  6.432 77.603 12.696 77.712 ;
     RECT  21.552 75.623 21.576 77.712 ;
  END
END dsfd_node_NNfd
END LIBRARY
